VERSION 5.7 ;
BUSBITCHARS "[]" ;
DIVIDERCHAR "/" ;

PROPERTYDEFINITIONS
  MACRO pkpIndependentSourceSHA256 STRING ;
  MACRO CatenaDesignType STRING ;
END PROPERTYDEFINITIONS

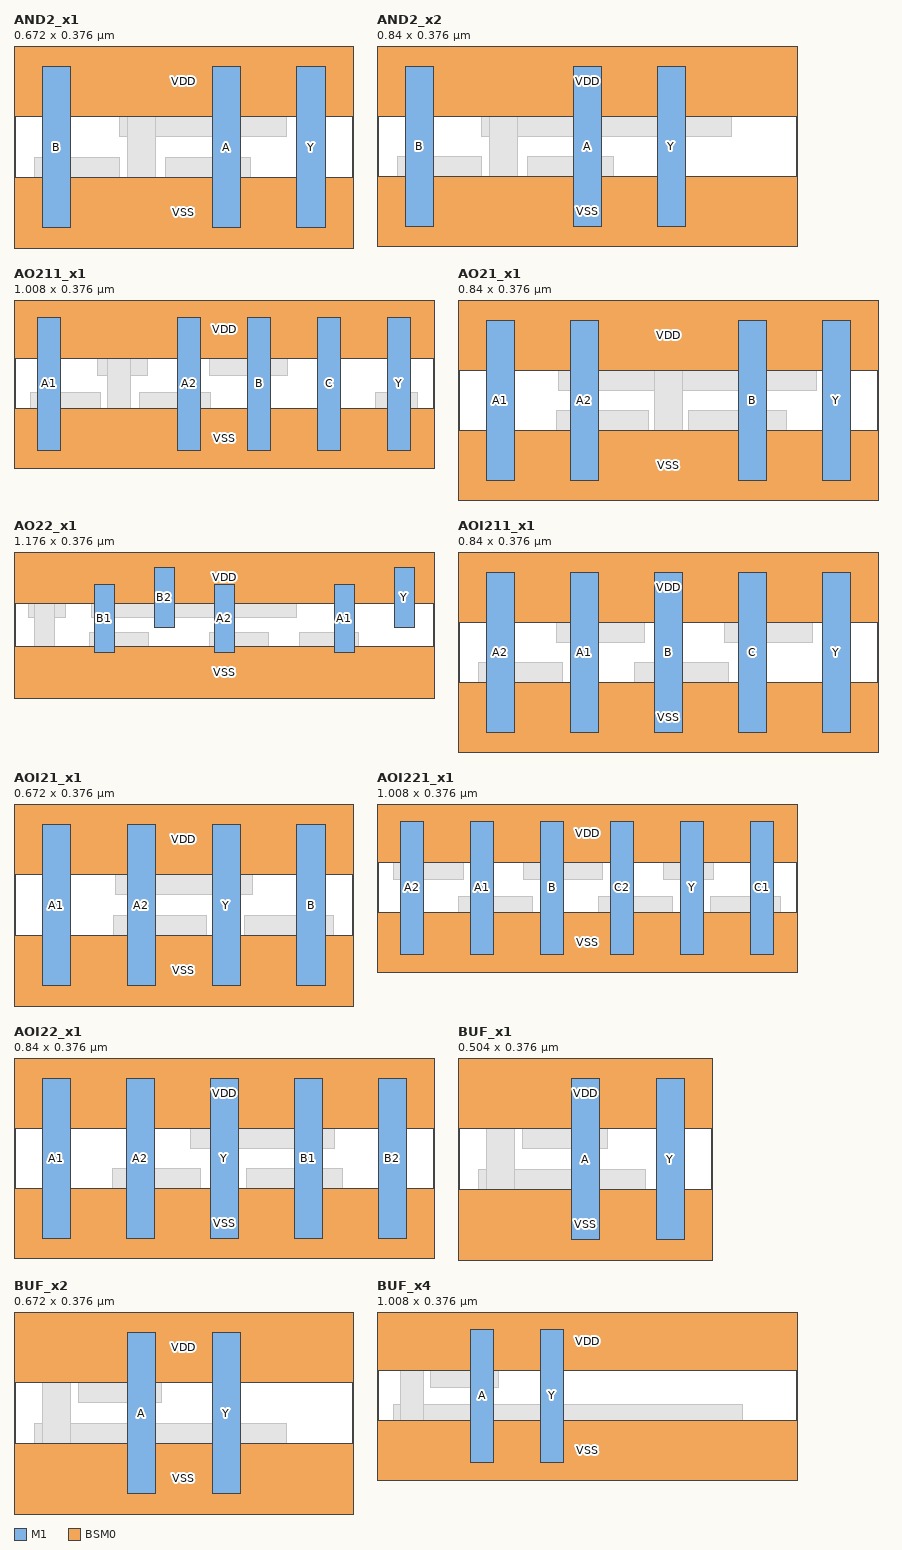
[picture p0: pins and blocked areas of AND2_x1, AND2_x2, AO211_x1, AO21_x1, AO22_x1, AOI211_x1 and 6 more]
MACRO AND2_x1
  CLASS CORE ;
  ORIGIN 0 0 ;
  FOREIGN AND2_x1 0 0 ;
  SIZE 0.672 BY 0.376 ;
  SYMMETRY X Y ;
  SITE CoreSite ;
  PIN A
    DIRECTION INPUT ;
    USE SIGNAL ;
    PORT
      LAYER M1 ;
        RECT 0.392 0.028 0.448 0.348 ;
    END
  END A
  PIN B
    DIRECTION INPUT ;
    USE SIGNAL ;
    PORT
      LAYER M1 ;
        RECT 0.056 0.028 0.112 0.348 ;
    END
  END B
  PIN Y
    DIRECTION OUTPUT ;
    USE SIGNAL ;
    PORT
      LAYER M1 ;
        RECT 0.56 0.028 0.616 0.348 ;
    END
  END Y
  PIN VDD
    DIRECTION INOUT ;
    USE POWER ;
    SHAPE ABUTMENT ;
    PORT
      LAYER BSM0 ;
        RECT 0 0.248 0.672 0.504 ;
    END
  END VDD
  PIN VSS
    DIRECTION INOUT ;
    USE GROUND ;
    SHAPE ABUTMENT ;
    PORT
      LAYER BSM0 ;
        RECT 0 -0.128 0.672 0.128 ;
    END
  END VSS
  OBS
    LAYER M0 ;
      RECT 0.532 0.04 0.632 0.084 ;
      RECT 0.532 0.292 0.632 0.336 ;
      RECT 0.208 0.208 0.54 0.252 ;
      RECT 0.3 0.124 0.468 0.168 ;
      RECT 0.04 0.04 0.32 0.084 ;
      RECT 0.2 0.292 0.32 0.336 ;
      RECT 0.04 0.124 0.208 0.168 ;
    LAYER M1 ;
      RECT 0.224 0.028 0.28 0.348 ;
  END
END AND2_x1

MACRO AND2_x2
  CLASS CORE ;
  ORIGIN 0 0 ;
  FOREIGN AND2_x2 0 0 ;
  SIZE 0.84 BY 0.376 ;
  SYMMETRY X Y ;
  SITE CoreSite ;
  PIN A
    DIRECTION INPUT ;
    USE SIGNAL ;
    PORT
      LAYER M1 ;
        RECT 0.392 0.028 0.448 0.348 ;
    END
  END A
  PIN B
    DIRECTION INPUT ;
    USE SIGNAL ;
    PORT
      LAYER M1 ;
        RECT 0.056 0.028 0.112 0.348 ;
    END
  END B
  PIN Y
    DIRECTION OUTPUT ;
    USE SIGNAL ;
    PORT
      LAYER M1 ;
        RECT 0.56 0.028 0.616 0.348 ;
    END
  END Y
  PIN VDD
    DIRECTION INOUT ;
    USE POWER ;
    SHAPE ABUTMENT ;
    PORT
      LAYER BSM0 ;
        RECT 0 0.248 0.84 0.504 ;
    END
  END VDD
  PIN VSS
    DIRECTION INOUT ;
    USE GROUND ;
    SHAPE ABUTMENT ;
    PORT
      LAYER BSM0 ;
        RECT 0 -0.128 0.84 0.128 ;
    END
  END VSS
  OBS
    LAYER M0 ;
      RECT 0.208 0.208 0.708 0.252 ;
      RECT 0.536 0.04 0.656 0.084 ;
      RECT 0.536 0.292 0.656 0.336 ;
      RECT 0.3 0.124 0.472 0.168 ;
      RECT 0.04 0.04 0.32 0.084 ;
      RECT 0.2 0.292 0.32 0.336 ;
      RECT 0.04 0.124 0.208 0.168 ;
    LAYER M1 ;
      RECT 0.224 0.028 0.28 0.348 ;
  END
END AND2_x2

MACRO AO211_x1
  CLASS CORE ;
  ORIGIN 0 0 ;
  FOREIGN AO211_x1 0 0 ;
  SIZE 1.008 BY 0.376 ;
  SYMMETRY X Y ;
  SITE CoreSite ;
  PIN A1
    DIRECTION INPUT ;
    USE SIGNAL ;
    PORT
      LAYER M1 ;
        RECT 0.056 0.028 0.112 0.348 ;
    END
  END A1
  PIN A2
    DIRECTION INPUT ;
    USE SIGNAL ;
    PORT
      LAYER M1 ;
        RECT 0.392 0.028 0.448 0.348 ;
    END
  END A2
  PIN B
    DIRECTION INPUT ;
    USE SIGNAL ;
    PORT
      LAYER M1 ;
        RECT 0.56 0.028 0.616 0.348 ;
    END
  END B
  PIN C
    DIRECTION INPUT ;
    USE SIGNAL ;
    PORT
      LAYER M1 ;
        RECT 0.728 0.028 0.784 0.348 ;
    END
  END C
  PIN Y
    DIRECTION OUTPUT ;
    USE SIGNAL ;
    PORT
      LAYER M1 ;
        RECT 0.896 0.028 0.952 0.348 ;
    END
  END Y
  PIN VDD
    DIRECTION INOUT ;
    USE POWER ;
    SHAPE ABUTMENT ;
    PORT
      LAYER BSM0 ;
        RECT 0 0.248 1.008 0.504 ;
    END
  END VDD
  PIN VSS
    DIRECTION INOUT ;
    USE GROUND ;
    SHAPE ABUTMENT ;
    PORT
      LAYER BSM0 ;
        RECT 0 -0.128 1.008 0.128 ;
    END
  END VSS
  OBS
    LAYER M0 ;
      RECT 0.868 0.124 0.968 0.168 ;
      RECT 0.868 0.292 0.968 0.336 ;
      RECT 0.04 0.04 0.876 0.084 ;
      RECT 0.636 0.292 0.796 0.336 ;
      RECT 0.468 0.208 0.656 0.252 ;
      RECT 0.3 0.124 0.472 0.168 ;
      RECT 0.048 0.292 0.456 0.336 ;
      RECT 0.2 0.208 0.32 0.252 ;
      RECT 0.04 0.124 0.208 0.168 ;
    LAYER M1 ;
      RECT 0.224 0.028 0.28 0.348 ;
  END
END AO211_x1

MACRO AO21_x1
  CLASS CORE ;
  ORIGIN 0 0 ;
  FOREIGN AO21_x1 0 0 ;
  SIZE 0.84 BY 0.376 ;
  SYMMETRY X Y ;
  SITE CoreSite ;
  PIN A1
    DIRECTION INPUT ;
    USE SIGNAL ;
    PORT
      LAYER M1 ;
        RECT 0.056 0.028 0.112 0.348 ;
    END
  END A1
  PIN A2
    DIRECTION INPUT ;
    USE SIGNAL ;
    PORT
      LAYER M1 ;
        RECT 0.224 0.028 0.28 0.348 ;
    END
  END A2
  PIN B
    DIRECTION INPUT ;
    USE SIGNAL ;
    PORT
      LAYER M1 ;
        RECT 0.56 0.028 0.616 0.348 ;
    END
  END B
  PIN Y
    DIRECTION OUTPUT ;
    USE SIGNAL ;
    PORT
      LAYER M1 ;
        RECT 0.728 0.028 0.784 0.348 ;
    END
  END Y
  PIN VDD
    DIRECTION INOUT ;
    USE POWER ;
    SHAPE ABUTMENT ;
    PORT
      LAYER BSM0 ;
        RECT 0 0.248 0.84 0.504 ;
    END
  END VDD
  PIN VSS
    DIRECTION INOUT ;
    USE GROUND ;
    SHAPE ABUTMENT ;
    PORT
      LAYER BSM0 ;
        RECT 0 -0.128 0.84 0.128 ;
    END
  END VSS
  OBS
    LAYER M0 ;
      RECT 0.688 0.04 0.8 0.084 ;
      RECT 0.688 0.292 0.8 0.336 ;
      RECT 0.2 0.208 0.716 0.252 ;
      RECT 0.46 0.124 0.656 0.168 ;
      RECT 0.352 0.04 0.476 0.084 ;
      RECT 0.04 0.292 0.468 0.336 ;
      RECT 0.196 0.124 0.38 0.168 ;
      RECT 0.04 0.04 0.212 0.084 ;
    LAYER M1 ;
      RECT 0.392 0.028 0.448 0.348 ;
  END
END AO21_x1

MACRO AO22_x1
  CLASS CORE ;
  ORIGIN 0 0 ;
  FOREIGN AO22_x1 0 0 ;
  SIZE 1.176 BY 0.376 ;
  SYMMETRY X Y ;
  SITE CoreSite ;
  PIN A1
    DIRECTION INPUT ;
    USE SIGNAL ;
    PORT
      LAYER M1 ;
        RECT 0.896 0.112 0.952 0.302 ;
    END
  END A1
  PIN A2
    DIRECTION INPUT ;
    USE SIGNAL ;
    PORT
      LAYER M1 ;
        RECT 0.56 0.112 0.616 0.302 ;
    END
  END A2
  PIN B1
    DIRECTION INPUT ;
    USE SIGNAL ;
    PORT
      LAYER M1 ;
        RECT 0.224 0.112 0.28 0.302 ;
    END
  END B1
  PIN B2
    DIRECTION INPUT ;
    USE SIGNAL ;
    PORT
      LAYER M1 ;
        RECT 0.392 0.18 0.448 0.348 ;
    END
  END B2
  PIN Y
    DIRECTION OUTPUT ;
    USE SIGNAL ;
    PORT
      LAYER M1 ;
        RECT 1.064 0.18 1.12 0.348 ;
    END
  END Y
  PIN VDD
    DIRECTION INOUT ;
    USE POWER ;
    SHAPE ABUTMENT ;
    PORT
      LAYER BSM0 ;
        RECT 0 0.248 1.176 0.504 ;
    END
  END VDD
  PIN VSS
    DIRECTION INOUT ;
    USE GROUND ;
    SHAPE ABUTMENT ;
    PORT
      LAYER BSM0 ;
        RECT 0 -0.128 1.176 0.128 ;
    END
  END VSS
  OBS
    LAYER M0 ;
      RECT 1.024 0.292 1.136 0.336 ;
      RECT 0.04 0.04 1.048 0.084 ;
      RECT 0.8 0.124 0.964 0.168 ;
      RECT 0.216 0.208 0.792 0.252 ;
      RECT 0.548 0.124 0.712 0.168 ;
      RECT 0.128 0.292 0.46 0.336 ;
      RECT 0.212 0.124 0.376 0.168 ;
      RECT 0.04 0.208 0.144 0.252 ;
    LAYER M1 ;
      RECT 0.056 0.028 0.112 0.304 ;
  END
  PROPERTY pkpIndependentSourceSHA256 "be00ef7e564fc46890b79b18678042070a181a3fd22f0e1ad2fda87f76c24992" ;
END AO22_x1

MACRO AOI211_x1
  CLASS CORE ;
  ORIGIN 0 0 ;
  FOREIGN AOI211_x1 0 0 ;
  SIZE 0.84 BY 0.376 ;
  SYMMETRY X Y ;
  SITE CoreSite ;
  PIN A1
    DIRECTION INPUT ;
    USE SIGNAL ;
    PORT
      LAYER M1 ;
        RECT 0.224 0.028 0.28 0.348 ;
    END
  END A1
  PIN A2
    DIRECTION INPUT ;
    USE SIGNAL ;
    PORT
      LAYER M1 ;
        RECT 0.056 0.028 0.112 0.348 ;
    END
  END A2
  PIN B
    DIRECTION INPUT ;
    USE SIGNAL ;
    PORT
      LAYER M1 ;
        RECT 0.392 0.028 0.448 0.348 ;
    END
  END B
  PIN C
    DIRECTION INPUT ;
    USE SIGNAL ;
    PORT
      LAYER M1 ;
        RECT 0.56 0.028 0.616 0.348 ;
    END
  END C
  PIN Y
    DIRECTION OUTPUT ;
    USE SIGNAL ;
    PORT
      LAYER M1 ;
        RECT 0.728 0.028 0.784 0.348 ;
    END
  END Y
  PIN VDD
    DIRECTION INOUT ;
    USE POWER ;
    SHAPE ABUTMENT ;
    PORT
      LAYER BSM0 ;
        RECT 0 0.248 0.84 0.504 ;
    END
  END VDD
  PIN VSS
    DIRECTION INOUT ;
    USE GROUND ;
    SHAPE ABUTMENT ;
    PORT
      LAYER BSM0 ;
        RECT 0 -0.128 0.84 0.128 ;
    END
  END VSS
  OBS
    LAYER M0 ;
      RECT 0.384 0.04 0.8 0.084 ;
      RECT 0.688 0.292 0.8 0.336 ;
      RECT 0.532 0.208 0.708 0.252 ;
      RECT 0.352 0.124 0.54 0.168 ;
      RECT 0.048 0.292 0.456 0.336 ;
      RECT 0.196 0.208 0.372 0.252 ;
      RECT 0.04 0.124 0.208 0.168 ;
  END
END AOI211_x1

MACRO AOI21_x1
  CLASS CORE ;
  ORIGIN 0 0 ;
  FOREIGN AOI21_x1 0 0 ;
  SIZE 0.672 BY 0.376 ;
  SYMMETRY X Y ;
  SITE CoreSite ;
  PIN A1
    DIRECTION INPUT ;
    USE SIGNAL ;
    PORT
      LAYER M1 ;
        RECT 0.056 0.028 0.112 0.348 ;
    END
  END A1
  PIN A2
    DIRECTION INPUT ;
    USE SIGNAL ;
    PORT
      LAYER M1 ;
        RECT 0.224 0.028 0.28 0.348 ;
    END
  END A2
  PIN B
    DIRECTION INPUT ;
    USE SIGNAL ;
    PORT
      LAYER M1 ;
        RECT 0.56 0.028 0.616 0.348 ;
    END
  END B
  PIN Y
    DIRECTION OUTPUT ;
    USE SIGNAL ;
    PORT
      LAYER M1 ;
        RECT 0.392 0.028 0.448 0.348 ;
    END
  END Y
  PIN VDD
    DIRECTION INOUT ;
    USE POWER ;
    SHAPE ABUTMENT ;
    PORT
      LAYER BSM0 ;
        RECT 0 0.248 0.672 0.504 ;
    END
  END VDD
  PIN VSS
    DIRECTION INOUT ;
    USE GROUND ;
    SHAPE ABUTMENT ;
    PORT
      LAYER BSM0 ;
        RECT 0 -0.128 0.672 0.128 ;
    END
  END VSS
  OBS
    LAYER M0 ;
      RECT 0.456 0.124 0.632 0.168 ;
      RECT 0.352 0.04 0.472 0.084 ;
      RECT 0.2 0.208 0.472 0.252 ;
      RECT 0.04 0.292 0.472 0.336 ;
      RECT 0.196 0.124 0.38 0.168 ;
      RECT 0.04 0.04 0.208 0.084 ;
  END
END AOI21_x1

MACRO AOI221_x1
  CLASS CORE ;
  ORIGIN 0 0 ;
  FOREIGN AOI221_x1 0 0 ;
  SIZE 1.008 BY 0.376 ;
  SYMMETRY X Y ;
  SITE CoreSite ;
  PIN A1
    DIRECTION INPUT ;
    USE SIGNAL ;
    PORT
      LAYER M1 ;
        RECT 0.224 0.028 0.28 0.348 ;
    END
  END A1
  PIN A2
    DIRECTION INPUT ;
    USE SIGNAL ;
    PORT
      LAYER M1 ;
        RECT 0.056 0.028 0.112 0.348 ;
    END
  END A2
  PIN B
    DIRECTION INPUT ;
    USE SIGNAL ;
    PORT
      LAYER M1 ;
        RECT 0.392 0.028 0.448 0.348 ;
    END
  END B
  PIN C1
    DIRECTION INPUT ;
    USE SIGNAL ;
    PORT
      LAYER M1 ;
        RECT 0.896 0.028 0.952 0.348 ;
    END
  END C1
  PIN C2
    DIRECTION INPUT ;
    USE SIGNAL ;
    PORT
      LAYER M1 ;
        RECT 0.56 0.028 0.616 0.348 ;
    END
  END C2
  PIN Y
    DIRECTION OUTPUT ;
    USE SIGNAL ;
    PORT
      LAYER M1 ;
        RECT 0.728 0.028 0.784 0.348 ;
    END
  END Y
  PIN VDD
    DIRECTION INOUT ;
    USE POWER ;
    SHAPE ABUTMENT ;
    PORT
      LAYER BSM0 ;
        RECT 0 0.248 1.008 0.504 ;
    END
  END VDD
  PIN VSS
    DIRECTION INOUT ;
    USE GROUND ;
    SHAPE ABUTMENT ;
    PORT
      LAYER BSM0 ;
        RECT 0 -0.128 1.008 0.128 ;
    END
  END VSS
  OBS
    LAYER M0 ;
      RECT 0.8 0.124 0.968 0.168 ;
      RECT 0.384 0.04 0.96 0.084 ;
      RECT 0.552 0.292 0.96 0.336 ;
      RECT 0.688 0.208 0.808 0.252 ;
      RECT 0.532 0.124 0.708 0.168 ;
      RECT 0.352 0.208 0.54 0.252 ;
      RECT 0.048 0.292 0.456 0.336 ;
      RECT 0.196 0.124 0.372 0.168 ;
      RECT 0.04 0.208 0.208 0.252 ;
  END
END AOI221_x1

MACRO AOI22_x1
  CLASS CORE ;
  ORIGIN 0 0 ;
  FOREIGN AOI22_x1 0 0 ;
  SIZE 0.84 BY 0.376 ;
  SYMMETRY X Y ;
  SITE CoreSite ;
  PIN A1
    DIRECTION INPUT ;
    USE SIGNAL ;
    PORT
      LAYER M1 ;
        RECT 0.056 0.028 0.112 0.348 ;
    END
  END A1
  PIN A2
    DIRECTION INPUT ;
    USE SIGNAL ;
    PORT
      LAYER M1 ;
        RECT 0.224 0.028 0.28 0.348 ;
    END
  END A2
  PIN B1
    DIRECTION INPUT ;
    USE SIGNAL ;
    PORT
      LAYER M1 ;
        RECT 0.56 0.028 0.616 0.348 ;
    END
  END B1
  PIN B2
    DIRECTION INPUT ;
    USE SIGNAL ;
    PORT
      LAYER M1 ;
        RECT 0.728 0.028 0.784 0.348 ;
    END
  END B2
  PIN Y
    DIRECTION OUTPUT ;
    USE SIGNAL ;
    PORT
      LAYER M1 ;
        RECT 0.392 0.028 0.448 0.348 ;
    END
  END Y
  PIN VDD
    DIRECTION INOUT ;
    USE POWER ;
    SHAPE ABUTMENT ;
    PORT
      LAYER BSM0 ;
        RECT 0 0.248 0.84 0.504 ;
    END
  END VDD
  PIN VSS
    DIRECTION INOUT ;
    USE GROUND ;
    SHAPE ABUTMENT ;
    PORT
      LAYER BSM0 ;
        RECT 0 -0.128 0.84 0.128 ;
    END
  END VSS
  OBS
    LAYER M0 ;
      RECT 0.624 0.04 0.8 0.084 ;
      RECT 0.04 0.292 0.8 0.336 ;
      RECT 0.464 0.124 0.656 0.168 ;
      RECT 0.352 0.208 0.64 0.252 ;
      RECT 0.352 0.04 0.476 0.084 ;
      RECT 0.196 0.124 0.372 0.168 ;
      RECT 0.044 0.04 0.208 0.084 ;
  END
  PROPERTY CatenaDesignType "deviceLevel" ;
END AOI22_x1

MACRO BUF_x1
  CLASS CORE ;
  ORIGIN 0 0 ;
  FOREIGN BUF_x1 0 0 ;
  SIZE 0.504 BY 0.376 ;
  SYMMETRY X Y ;
  SITE CoreSite ;
  PIN A
    DIRECTION INPUT ;
    USE SIGNAL ;
    PORT
      LAYER M1 ;
        RECT 0.224 0.028 0.28 0.348 ;
    END
  END A
  PIN Y
    DIRECTION OUTPUT ;
    USE SIGNAL ;
    PORT
      LAYER M1 ;
        RECT 0.392 0.028 0.448 0.348 ;
    END
  END Y
  PIN VDD
    DIRECTION INOUT ;
    USE POWER ;
    SHAPE ABUTMENT ;
    PORT
      LAYER BSM0 ;
        RECT 0 0.248 0.504 0.504 ;
    END
  END VDD
  PIN VSS
    DIRECTION INOUT ;
    USE GROUND ;
    SHAPE ABUTMENT ;
    PORT
      LAYER BSM0 ;
        RECT 0 -0.128 0.504 0.128 ;
    END
  END VSS
  OBS
    LAYER M0 ;
      RECT 0.352 0.04 0.464 0.084 ;
      RECT 0.352 0.292 0.464 0.336 ;
      RECT 0.04 0.124 0.372 0.168 ;
      RECT 0.128 0.208 0.296 0.252 ;
      RECT 0.04 0.04 0.14 0.084 ;
      RECT 0.04 0.292 0.14 0.336 ;
    LAYER M1 ;
      RECT 0.056 0.028 0.112 0.348 ;
  END
END BUF_x1

MACRO BUF_x2
  CLASS CORE ;
  ORIGIN 0 0 ;
  FOREIGN BUF_x2 0 0 ;
  SIZE 0.672 BY 0.376 ;
  SYMMETRY X Y ;
  SITE CoreSite ;
  PIN A
    DIRECTION INPUT ;
    USE SIGNAL ;
    PORT
      LAYER M1 ;
        RECT 0.224 0.028 0.28 0.348 ;
    END
  END A
  PIN Y
    DIRECTION OUTPUT ;
    USE SIGNAL ;
    PORT
      LAYER M1 ;
        RECT 0.392 0.028 0.448 0.348 ;
    END
  END Y
  PIN VDD
    DIRECTION INOUT ;
    USE POWER ;
    SHAPE ABUTMENT ;
    PORT
      LAYER BSM0 ;
        RECT 0 0.248 0.672 0.504 ;
    END
  END VDD
  PIN VSS
    DIRECTION INOUT ;
    USE GROUND ;
    SHAPE ABUTMENT ;
    PORT
      LAYER BSM0 ;
        RECT 0 -0.128 0.672 0.128 ;
    END
  END VSS
  OBS
    LAYER M0 ;
      RECT 0.04 0.124 0.54 0.168 ;
      RECT 0.352 0.04 0.472 0.084 ;
      RECT 0.352 0.292 0.472 0.336 ;
      RECT 0.128 0.208 0.292 0.252 ;
      RECT 0.04 0.04 0.14 0.084 ;
      RECT 0.04 0.292 0.14 0.336 ;
    LAYER M1 ;
      RECT 0.056 0.028 0.112 0.348 ;
  END
END BUF_x2

MACRO BUF_x4
  CLASS CORE ;
  ORIGIN 0 0 ;
  FOREIGN BUF_x4 0 0 ;
  SIZE 1.008 BY 0.376 ;
  SYMMETRY X Y ;
  SITE CoreSite ;
  PIN A
    DIRECTION INPUT ;
    USE SIGNAL ;
    PORT
      LAYER M1 ;
        RECT 0.224 0.028 0.28 0.348 ;
    END
  END A
  PIN Y
    DIRECTION OUTPUT ;
    USE SIGNAL ;
    PORT
      LAYER M1 ;
        RECT 0.392 0.028 0.448 0.348 ;
    END
  END Y
  PIN VDD
    DIRECTION INOUT ;
    USE POWER ;
    SHAPE ABUTMENT ;
    PORT
      LAYER BSM0 ;
        RECT 0 0.248 1.008 0.504 ;
    END
  END VDD
  PIN VSS
    DIRECTION INOUT ;
    USE GROUND ;
    SHAPE ABUTMENT ;
    PORT
      LAYER BSM0 ;
        RECT 0 -0.128 1.008 0.128 ;
    END
  END VSS
  OBS
    LAYER M0 ;
      RECT 0.04 0.124 0.876 0.168 ;
      RECT 0.368 0.04 0.796 0.084 ;
      RECT 0.368 0.292 0.796 0.336 ;
      RECT 0.128 0.208 0.292 0.252 ;
      RECT 0.04 0.04 0.14 0.084 ;
      RECT 0.04 0.292 0.14 0.336 ;
    LAYER M1 ;
      RECT 0.056 0.028 0.112 0.348 ;
  END
END BUF_x4

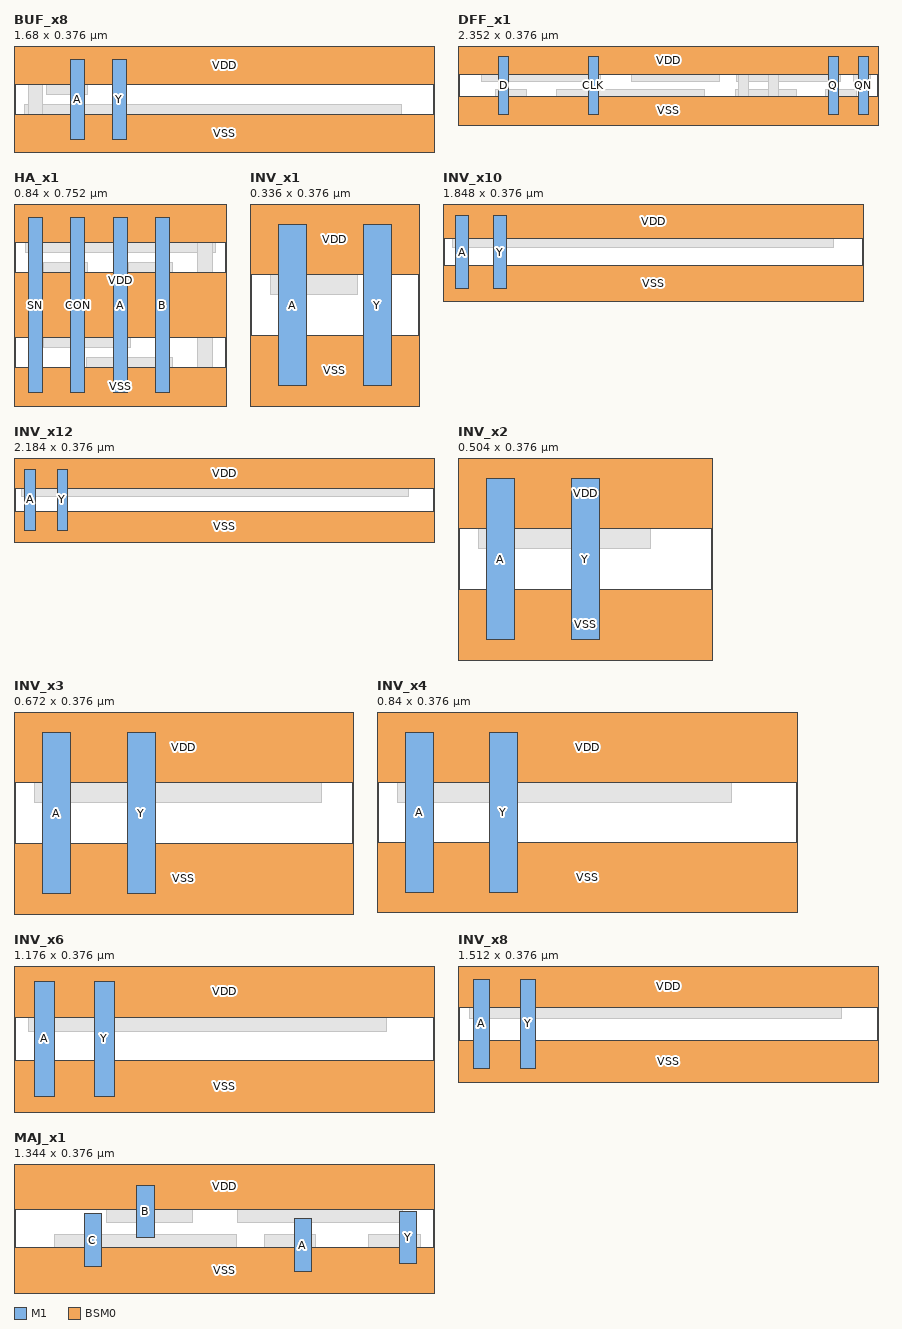
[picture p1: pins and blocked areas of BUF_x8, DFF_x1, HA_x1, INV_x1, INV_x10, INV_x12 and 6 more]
MACRO BUF_x8
  CLASS CORE ;
  ORIGIN 0 0 ;
  FOREIGN BUF_x8 0 0 ;
  SIZE 1.68 BY 0.376 ;
  SYMMETRY X Y ;
  SITE CoreSite ;
  PIN A
    DIRECTION INPUT ;
    USE SIGNAL ;
    PORT
      LAYER M1 ;
        RECT 0.224 0.028 0.28 0.348 ;
    END
  END A
  PIN Y
    DIRECTION OUTPUT ;
    USE SIGNAL ;
    PORT
      LAYER M1 ;
        RECT 0.392 0.028 0.448 0.348 ;
    END
  END Y
  PIN VDD
    DIRECTION INOUT ;
    USE POWER ;
    SHAPE ABUTMENT ;
    PORT
      LAYER BSM0 ;
        RECT 0 0.248 1.68 0.504 ;
    END
  END VDD
  PIN VSS
    DIRECTION INOUT ;
    USE GROUND ;
    SHAPE ABUTMENT ;
    PORT
      LAYER BSM0 ;
        RECT 0 -0.128 1.68 0.128 ;
    END
  END VSS
  OBS
    LAYER M0 ;
      RECT 0.04 0.124 1.548 0.168 ;
      RECT 0.368 0.04 1.468 0.084 ;
      RECT 0.368 0.292 1.468 0.336 ;
      RECT 0.128 0.208 0.292 0.252 ;
      RECT 0.04 0.04 0.14 0.084 ;
      RECT 0.04 0.292 0.14 0.336 ;
    LAYER M1 ;
      RECT 0.056 0.028 0.112 0.348 ;
  END
END BUF_x8

MACRO DFF_x1
  CLASS CORE ;
  ORIGIN 0 0 ;
  FOREIGN DFF_x1 0 0 ;
  SIZE 2.352 BY 0.376 ;
  SYMMETRY X Y ;
  SITE CoreSite ;
  PIN CLK
    DIRECTION INPUT ;
    USE CLOCK ;
    PORT
      LAYER M1 ;
        RECT 0.728 0.028 0.784 0.348 ;
    END
  END CLK
  PIN D
    DIRECTION INPUT ;
    USE SIGNAL ;
    PORT
      LAYER M1 ;
        RECT 0.224 0.028 0.28 0.348 ;
    END
  END D
  PIN Q
    DIRECTION OUTPUT ;
    USE SIGNAL ;
    PORT
      LAYER M1 ;
        RECT 2.072 0.028 2.128 0.348 ;
    END
  END Q
  PIN QN
    DIRECTION OUTPUT ;
    USE SIGNAL ;
    PORT
      LAYER M1 ;
        RECT 2.24 0.028 2.296 0.348 ;
    END
  END QN
  PIN VDD
    DIRECTION INOUT ;
    USE POWER ;
    SHAPE ABUTMENT ;
    PORT
      LAYER BSM0 ;
        RECT 0 0.248 2.352 0.504 ;
    END
  END VDD
  PIN VSS
    DIRECTION INOUT ;
    USE GROUND ;
    SHAPE ABUTMENT ;
    PORT
      LAYER BSM0 ;
        RECT 0 -0.128 2.352 0.128 ;
    END
  END VSS
  OBS
    LAYER M0 ;
      RECT 2.212 0.208 2.312 0.252 ;
      RECT 1.98 0.04 2.308 0.084 ;
      RECT 2.06 0.124 2.234 0.168 ;
      RECT 1.56 0.208 2.14 0.252 ;
      RECT 1.556 0.124 1.898 0.168 ;
      RECT 1.724 0.292 1.898 0.336 ;
      RECT 0.716 0.04 1.804 0.084 ;
      RECT 0.048 0.292 1.636 0.336 ;
      RECT 0.972 0.208 1.464 0.252 ;
      RECT 0.552 0.124 1.38 0.168 ;
      RECT 0.132 0.208 0.796 0.252 ;
      RECT 0.048 0.04 0.54 0.084 ;
      RECT 0.212 0.124 0.386 0.168 ;
    LAYER M1 ;
      RECT 1.736 0.028 1.792 0.348 ;
      RECT 1.568 0.028 1.624 0.348 ;
  END
END DFF_x1

MACRO HA_x1
  CLASS CORE ;
  ORIGIN 0 0 ;
  FOREIGN HA_x1 0 0 ;
  SIZE 0.84 BY 0.752 ;
  SYMMETRY X Y ;
  SITE CoreSite ;
  PIN A
    DIRECTION INPUT ;
    USE SIGNAL ;
    PORT
      LAYER M1 ;
        RECT 0.392 0.028 0.448 0.724 ;
    END
  END A
  PIN B
    DIRECTION INPUT ;
    USE SIGNAL ;
    PORT
      LAYER M1 ;
        RECT 0.56 0.028 0.616 0.724 ;
    END
  END B
  PIN CON
    DIRECTION OUTPUT ;
    USE SIGNAL ;
    PORT
      LAYER M1 ;
        RECT 0.224 0.028 0.28 0.724 ;
    END
  END CON
  PIN SN
    DIRECTION OUTPUT ;
    USE SIGNAL ;
    PORT
      LAYER M1 ;
        RECT 0.056 0.028 0.112 0.724 ;
    END
  END SN
  PIN VDD
    DIRECTION INOUT ;
    USE POWER ;
    SHAPE ABUTMENT ;
    PORT
      LAYER BSM0 ;
        RECT 0 0.248 0.84 0.504 ;
    END
  END VDD
  PIN VSS
    DIRECTION INOUT ;
    USE GROUND ;
    SHAPE ABUTMENT ;
    PORT
      LAYER BSM0 ;
        RECT 0 -0.128 0.84 0.128 ;
        RECT 0 0.624 0.84 0.88 ;
    END
  END VSS
  OBS
    LAYER M0 ;
      RECT 0.538 0.416 0.796 0.46 ;
      RECT 0.044 0.584 0.796 0.628 ;
      RECT 0.286 0.124 0.628 0.168 ;
      RECT 0.454 0.5 0.628 0.544 ;
      RECT 0.216 0.668 0.624 0.712 ;
      RECT 0.212 0.04 0.47 0.084 ;
      RECT 0.118 0.208 0.46 0.252 ;
      RECT 0.286 0.416 0.46 0.46 ;
      RECT 0.048 0.292 0.456 0.336 ;
      RECT 0.118 0.5 0.292 0.544 ;
      RECT 0.04 0.416 0.14 0.46 ;
    LAYER M1 ;
      RECT 0.728 0.028 0.784 0.724 ;
  END
END HA_x1

MACRO INV_x1
  CLASS CORE ;
  ORIGIN 0 0 ;
  FOREIGN INV_x1 0 0 ;
  SIZE 0.336 BY 0.376 ;
  SYMMETRY X Y ;
  SITE CoreSite ;
  PIN A
    DIRECTION INPUT ;
    USE SIGNAL ;
    PORT
      LAYER M1 ;
        RECT 0.056 0.028 0.112 0.348 ;
    END
  END A
  PIN Y
    DIRECTION OUTPUT ;
    USE SIGNAL ;
    PORT
      LAYER M1 ;
        RECT 0.224 0.028 0.28 0.348 ;
    END
  END Y
  PIN VDD
    DIRECTION INOUT ;
    USE POWER ;
    SHAPE ABUTMENT ;
    PORT
      LAYER BSM0 ;
        RECT 0 0.248 0.336 0.504 ;
    END
  END VDD
  PIN VSS
    DIRECTION INOUT ;
    USE GROUND ;
    SHAPE ABUTMENT ;
    PORT
      LAYER BSM0 ;
        RECT 0 -0.128 0.336 0.128 ;
    END
  END VSS
  OBS
    LAYER M0 ;
      RECT 0.128 0.04 0.296 0.084 ;
      RECT 0.128 0.292 0.296 0.336 ;
      RECT 0.04 0.208 0.212 0.252 ;
  END
END INV_x1

MACRO INV_x10
  CLASS CORE ;
  ORIGIN 0 0 ;
  FOREIGN INV_x10 0 0 ;
  SIZE 1.848 BY 0.376 ;
  SYMMETRY X Y ;
  SITE CoreSite ;
  PIN A
    DIRECTION INPUT ;
    USE SIGNAL ;
    PORT
      LAYER M1 ;
        RECT 0.056 0.028 0.112 0.348 ;
    END
  END A
  PIN Y
    DIRECTION OUTPUT ;
    USE SIGNAL ;
    PORT
      LAYER M1 ;
        RECT 0.224 0.028 0.28 0.348 ;
    END
  END Y
  PIN VDD
    DIRECTION INOUT ;
    USE POWER ;
    SHAPE ABUTMENT ;
    PORT
      LAYER BSM0 ;
        RECT 0 0.248 1.848 0.504 ;
    END
  END VDD
  PIN VSS
    DIRECTION INOUT ;
    USE GROUND ;
    SHAPE ABUTMENT ;
    PORT
      LAYER BSM0 ;
        RECT 0 -0.128 1.848 0.128 ;
    END
  END VSS
  OBS
    LAYER M0 ;
      RECT 0.04 0.208 1.716 0.252 ;
      RECT 0.2 0.04 1.64 0.084 ;
      RECT 0.2 0.292 1.636 0.336 ;
  END
END INV_x10

MACRO INV_x12
  CLASS CORE ;
  ORIGIN 0 0 ;
  FOREIGN INV_x12 0 0 ;
  SIZE 2.184 BY 0.376 ;
  SYMMETRY X Y ;
  SITE CoreSite ;
  PIN A
    DIRECTION INPUT ;
    USE SIGNAL ;
    PORT
      LAYER M1 ;
        RECT 0.056 0.028 0.112 0.348 ;
    END
  END A
  PIN Y
    DIRECTION OUTPUT ;
    USE SIGNAL ;
    PORT
      LAYER M1 ;
        RECT 0.224 0.028 0.28 0.348 ;
    END
  END Y
  PIN VDD
    DIRECTION INOUT ;
    USE POWER ;
    SHAPE ABUTMENT ;
    PORT
      LAYER BSM0 ;
        RECT 0 0.248 2.184 0.504 ;
    END
  END VDD
  PIN VSS
    DIRECTION INOUT ;
    USE GROUND ;
    SHAPE ABUTMENT ;
    PORT
      LAYER BSM0 ;
        RECT 0 -0.128 2.184 0.128 ;
    END
  END VSS
  OBS
    LAYER M0 ;
      RECT 0.04 0.208 2.052 0.252 ;
      RECT 0.2 0.04 1.972 0.084 ;
      RECT 0.2 0.292 1.972 0.336 ;
  END
END INV_x12

MACRO INV_x2
  CLASS CORE ;
  ORIGIN 0 0 ;
  FOREIGN INV_x2 0 0 ;
  SIZE 0.504 BY 0.376 ;
  SYMMETRY X Y ;
  SITE CoreSite ;
  PIN A
    DIRECTION INPUT ;
    USE SIGNAL ;
    PORT
      LAYER M1 ;
        RECT 0.056 0.028 0.112 0.348 ;
    END
  END A
  PIN Y
    DIRECTION OUTPUT ;
    USE SIGNAL ;
    PORT
      LAYER M1 ;
        RECT 0.224 0.028 0.28 0.348 ;
    END
  END Y
  PIN VDD
    DIRECTION INOUT ;
    USE POWER ;
    SHAPE ABUTMENT ;
    PORT
      LAYER BSM0 ;
        RECT 0 0.248 0.504 0.504 ;
    END
  END VDD
  PIN VSS
    DIRECTION INOUT ;
    USE GROUND ;
    SHAPE ABUTMENT ;
    PORT
      LAYER BSM0 ;
        RECT 0 -0.128 0.504 0.128 ;
    END
  END VSS
  OBS
    LAYER M0 ;
      RECT 0.04 0.208 0.38 0.252 ;
      RECT 0.2 0.04 0.32 0.084 ;
      RECT 0.2 0.292 0.32 0.336 ;
  END
END INV_x2

MACRO INV_x3
  CLASS CORE ;
  ORIGIN 0 0 ;
  FOREIGN INV_x3 0 0 ;
  SIZE 0.672 BY 0.376 ;
  SYMMETRY X Y ;
  SITE CoreSite ;
  PIN A
    DIRECTION INPUT ;
    USE SIGNAL ;
    PORT
      LAYER M1 ;
        RECT 0.056 0.028 0.112 0.348 ;
    END
  END A
  PIN Y
    DIRECTION OUTPUT ;
    USE SIGNAL ;
    PORT
      LAYER M1 ;
        RECT 0.224 0.028 0.28 0.348 ;
    END
  END Y
  PIN VDD
    DIRECTION INOUT ;
    USE POWER ;
    SHAPE ABUTMENT ;
    PORT
      LAYER BSM0 ;
        RECT 0 0.248 0.672 0.504 ;
    END
  END VDD
  PIN VSS
    DIRECTION INOUT ;
    USE GROUND ;
    SHAPE ABUTMENT ;
    PORT
      LAYER BSM0 ;
        RECT 0 -0.128 0.672 0.128 ;
    END
  END VSS
  OBS
    LAYER M0 ;
      RECT 0.2 0.04 0.628 0.084 ;
      RECT 0.2 0.292 0.628 0.336 ;
      RECT 0.04 0.208 0.608 0.252 ;
  END
END INV_x3

MACRO INV_x4
  CLASS CORE ;
  ORIGIN 0 0 ;
  FOREIGN INV_x4 0 0 ;
  SIZE 0.84 BY 0.376 ;
  SYMMETRY X Y ;
  SITE CoreSite ;
  PIN A
    DIRECTION INPUT ;
    USE SIGNAL ;
    PORT
      LAYER M1 ;
        RECT 0.056 0.028 0.112 0.348 ;
    END
  END A
  PIN Y
    DIRECTION OUTPUT ;
    USE SIGNAL ;
    PORT
      LAYER M1 ;
        RECT 0.224 0.028 0.28 0.348 ;
    END
  END Y
  PIN VDD
    DIRECTION INOUT ;
    USE POWER ;
    SHAPE ABUTMENT ;
    PORT
      LAYER BSM0 ;
        RECT 0 0.248 0.84 0.504 ;
    END
  END VDD
  PIN VSS
    DIRECTION INOUT ;
    USE GROUND ;
    SHAPE ABUTMENT ;
    PORT
      LAYER BSM0 ;
        RECT 0 -0.128 0.84 0.128 ;
    END
  END VSS
  OBS
    LAYER M0 ;
      RECT 0.04 0.208 0.708 0.252 ;
      RECT 0.2 0.04 0.628 0.084 ;
      RECT 0.2 0.292 0.628 0.336 ;
  END
END INV_x4

MACRO INV_x6
  CLASS CORE ;
  ORIGIN 0 0 ;
  FOREIGN INV_x6 0 0 ;
  SIZE 1.176 BY 0.376 ;
  SYMMETRY X Y ;
  SITE CoreSite ;
  PIN A
    DIRECTION INPUT ;
    USE SIGNAL ;
    PORT
      LAYER M1 ;
        RECT 0.056 0.028 0.112 0.348 ;
    END
  END A
  PIN Y
    DIRECTION OUTPUT ;
    USE SIGNAL ;
    PORT
      LAYER M1 ;
        RECT 0.224 0.028 0.28 0.348 ;
    END
  END Y
  PIN VDD
    DIRECTION INOUT ;
    USE POWER ;
    SHAPE ABUTMENT ;
    PORT
      LAYER BSM0 ;
        RECT 0 0.248 1.176 0.504 ;
    END
  END VDD
  PIN VSS
    DIRECTION INOUT ;
    USE GROUND ;
    SHAPE ABUTMENT ;
    PORT
      LAYER BSM0 ;
        RECT 0 -0.128 1.176 0.128 ;
    END
  END VSS
  OBS
    LAYER M0 ;
      RECT 0.04 0.208 1.044 0.252 ;
      RECT 0.2 0.04 0.964 0.084 ;
      RECT 0.2 0.292 0.964 0.336 ;
  END
END INV_x6

MACRO INV_x8
  CLASS CORE ;
  ORIGIN 0 0 ;
  FOREIGN INV_x8 0 0 ;
  SIZE 1.512 BY 0.376 ;
  SYMMETRY X Y ;
  SITE CoreSite ;
  PIN A
    DIRECTION INPUT ;
    USE SIGNAL ;
    PORT
      LAYER M1 ;
        RECT 0.056 0.028 0.112 0.348 ;
    END
  END A
  PIN Y
    DIRECTION OUTPUT ;
    USE SIGNAL ;
    PORT
      LAYER M1 ;
        RECT 0.224 0.028 0.28 0.348 ;
    END
  END Y
  PIN VDD
    DIRECTION INOUT ;
    USE POWER ;
    SHAPE ABUTMENT ;
    PORT
      LAYER BSM0 ;
        RECT 0 0.248 1.512 0.504 ;
    END
  END VDD
  PIN VSS
    DIRECTION INOUT ;
    USE GROUND ;
    SHAPE ABUTMENT ;
    PORT
      LAYER BSM0 ;
        RECT 0 -0.128 1.512 0.128 ;
    END
  END VSS
  OBS
    LAYER M0 ;
      RECT 0.04 0.208 1.38 0.252 ;
      RECT 0.2 0.04 1.3 0.084 ;
      RECT 0.2 0.292 1.3 0.336 ;
  END
END INV_x8

MACRO MAJ_x1
  CLASS CORE ;
  ORIGIN 0 0 ;
  FOREIGN MAJ_x1 0 0 ;
  SIZE 1.344 BY 0.376 ;
  SYMMETRY X Y ;
  SITE CoreSite ;
  PIN A
    DIRECTION INPUT ;
    USE SIGNAL ;
    PORT
      LAYER M1 ;
        RECT 0.896 0.05 0.952 0.218 ;
    END
  END A
  PIN B
    DIRECTION INPUT ;
    USE SIGNAL ;
    PORT
      LAYER M1 ;
        RECT 0.392 0.158 0.448 0.326 ;
    END
  END B
  PIN C
    DIRECTION INPUT ;
    USE SIGNAL ;
    PORT
      LAYER M1 ;
        RECT 0.224 0.066 0.28 0.234 ;
    END
  END C
  PIN Y
    DIRECTION OUTPUT ;
    USE SIGNAL ;
    PORT
      LAYER M1 ;
        RECT 1.232 0.074 1.288 0.242 ;
    END
  END Y
  PIN VDD
    DIRECTION INOUT ;
    USE POWER ;
    SHAPE ABUTMENT ;
    PORT
      LAYER BSM0 ;
        RECT 0 0.248 1.344 0.504 ;
    END
  END VDD
  PIN VSS
    DIRECTION INOUT ;
    USE GROUND ;
    SHAPE ABUTMENT ;
    PORT
      LAYER BSM0 ;
        RECT 0 -0.128 1.344 0.128 ;
    END
  END VSS
  OBS
    LAYER M0 ;
      RECT 1.136 0.124 1.3 0.168 ;
      RECT 0.716 0.208 1.244 0.252 ;
      RECT 0.212 0.292 1.02 0.336 ;
      RECT 0.212 0.04 0.964 0.084 ;
      RECT 0.8 0.124 0.964 0.168 ;
      RECT 0.128 0.124 0.712 0.168 ;
      RECT 0.296 0.208 0.572 0.252 ;
  END
  PROPERTY pkpIndependentSourceSHA256 "c6524f313f9f278eef24616a36d5740bf9d2db56e62a49f5a092eda3790d412a" ;
END MAJ_x1

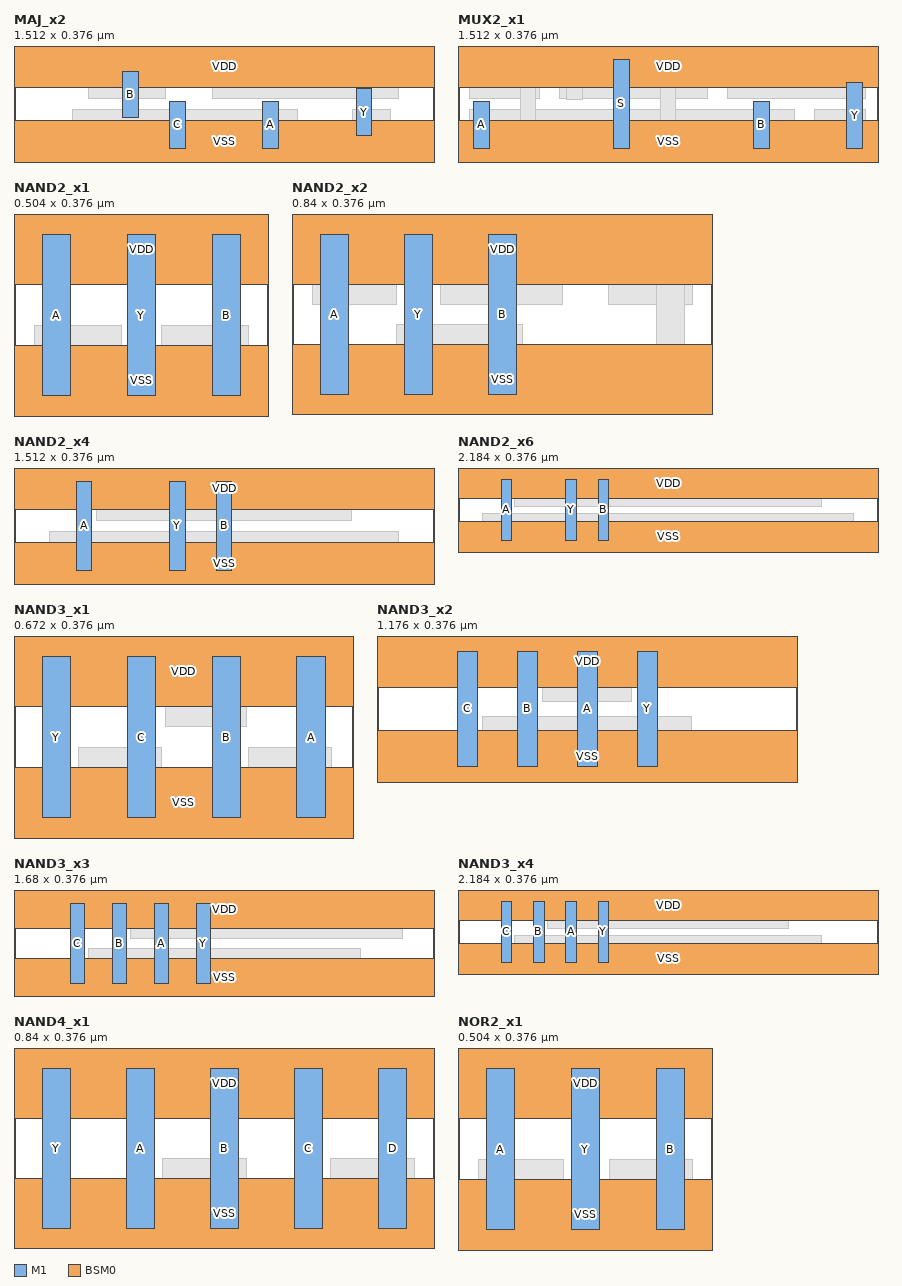
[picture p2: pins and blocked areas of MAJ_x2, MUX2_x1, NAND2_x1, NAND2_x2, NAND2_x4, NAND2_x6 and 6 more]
MACRO MAJ_x2
  CLASS CORE ;
  ORIGIN 0 0 ;
  FOREIGN MAJ_x2 0 0 ;
  SIZE 1.512 BY 0.376 ;
  SYMMETRY X Y ;
  SITE CoreSite ;
  PIN A
    DIRECTION INPUT ;
    USE SIGNAL ;
    PORT
      LAYER M1 ;
        RECT 0.896 0.028 0.952 0.196 ;
    END
  END A
  PIN B
    DIRECTION INPUT ;
    USE SIGNAL ;
    PORT
      LAYER M1 ;
        RECT 0.392 0.138 0.448 0.306 ;
    END
  END B
  PIN C
    DIRECTION INPUT ;
    USE SIGNAL ;
    PORT
      LAYER M1 ;
        RECT 0.56 0.028 0.616 0.196 ;
    END
  END C
  PIN Y
    DIRECTION OUTPUT ;
    USE SIGNAL ;
    PORT
      LAYER M1 ;
        RECT 1.232 0.074 1.288 0.242 ;
    END
  END Y
  PIN VDD
    DIRECTION INOUT ;
    USE POWER ;
    SHAPE ABUTMENT ;
    PORT
      LAYER BSM0 ;
        RECT 0 0.248 1.512 0.504 ;
    END
  END VDD
  PIN VSS
    DIRECTION INOUT ;
    USE GROUND ;
    SHAPE ABUTMENT ;
    PORT
      LAYER BSM0 ;
        RECT 0 -0.128 1.512 0.128 ;
    END
  END VSS
  OBS
    LAYER M0 ;
      RECT 0.716 0.208 1.384 0.252 ;
      RECT 1.22 0.124 1.356 0.168 ;
      RECT 0.212 0.124 1.02 0.168 ;
      RECT 0.8 0.04 0.964 0.084 ;
      RECT 0.212 0.292 0.964 0.336 ;
      RECT 0.128 0.04 0.712 0.084 ;
      RECT 0.268 0.208 0.544 0.252 ;
  END
  PROPERTY pkpIndependentSourceSHA256 "503b818806f41a63dad2466f29618c257b77dd42f9f3fecf4337ea01a5ae6336" ;
END MAJ_x2

MACRO MUX2_x1
  CLASS CORE ;
  ORIGIN 0 0 ;
  FOREIGN MUX2_x1 0 0 ;
  SIZE 1.512 BY 0.376 ;
  SYMMETRY X Y ;
  SITE CoreSite ;
  PIN A
    DIRECTION INPUT ;
    USE SIGNAL ;
    PORT
      LAYER M1 ;
        RECT 0.056 0.028 0.112 0.196 ;
    END
  END A
  PIN B
    DIRECTION INPUT ;
    USE SIGNAL ;
    PORT
      LAYER M1 ;
        RECT 1.064 0.028 1.12 0.196 ;
    END
  END B
  PIN S
    DIRECTION INPUT ;
    USE SIGNAL ;
    PORT
      LAYER M1 ;
        RECT 0.56 0.028 0.616 0.348 ;
    END
  END S
  PIN Y
    DIRECTION OUTPUT ;
    USE SIGNAL ;
    PORT
      LAYER M1 ;
        RECT 1.4 0.028 1.456 0.264 ;
    END
  END Y
  PIN VDD
    DIRECTION INOUT ;
    USE POWER ;
    SHAPE ABUTMENT ;
    PORT
      LAYER BSM0 ;
        RECT 0 0.248 1.512 0.504 ;
    END
  END VDD
  PIN VSS
    DIRECTION INOUT ;
    USE GROUND ;
    SHAPE ABUTMENT ;
    PORT
      LAYER BSM0 ;
        RECT 0 -0.128 1.512 0.128 ;
    END
  END VSS
  OBS
    LAYER M0 ;
      RECT 1.284 0.124 1.468 0.168 ;
      RECT 0.97 0.208 1.468 0.252 ;
      RECT 0.696 0.292 1.384 0.336 ;
      RECT 0.972 0.04 1.214 0.084 ;
      RECT 0.04 0.124 1.212 0.168 ;
      RECT 0.7 0.04 0.9 0.084 ;
      RECT 0.364 0.208 0.898 0.252 ;
      RECT 0.444 0.04 0.628 0.084 ;
      RECT 0.132 0.292 0.624 0.336 ;
      RECT 0.04 0.04 0.372 0.084 ;
      RECT 0.04 0.208 0.292 0.252 ;
    LAYER M1 ;
      RECT 0.728 0.028 0.784 0.348 ;
      RECT 0.392 0.204 0.448 0.348 ;
      RECT 0.224 0.028 0.28 0.264 ;
  END
END MUX2_x1

MACRO NAND2_x1
  CLASS CORE ;
  ORIGIN 0 0 ;
  FOREIGN NAND2_x1 0 0 ;
  SIZE 0.504 BY 0.376 ;
  SYMMETRY X Y ;
  SITE CoreSite ;
  PIN A
    DIRECTION INPUT ;
    USE SIGNAL ;
    PORT
      LAYER M1 ;
        RECT 0.056 0.028 0.112 0.348 ;
    END
  END A
  PIN B
    DIRECTION INPUT ;
    USE SIGNAL ;
    PORT
      LAYER M1 ;
        RECT 0.392 0.028 0.448 0.348 ;
    END
  END B
  PIN Y
    DIRECTION OUTPUT ;
    USE SIGNAL ;
    PORT
      LAYER M1 ;
        RECT 0.224 0.028 0.28 0.348 ;
    END
  END Y
  PIN VDD
    DIRECTION INOUT ;
    USE POWER ;
    SHAPE ABUTMENT ;
    PORT
      LAYER BSM0 ;
        RECT 0 0.248 0.504 0.504 ;
    END
  END VDD
  PIN VSS
    DIRECTION INOUT ;
    USE GROUND ;
    SHAPE ABUTMENT ;
    PORT
      LAYER BSM0 ;
        RECT 0 -0.128 0.504 0.128 ;
    END
  END VSS
  OBS
    LAYER M0 ;
      RECT 0.208 0.04 0.464 0.084 ;
      RECT 0.292 0.124 0.464 0.168 ;
      RECT 0.04 0.292 0.464 0.336 ;
      RECT 0.04 0.124 0.212 0.168 ;
  END
END NAND2_x1

MACRO NAND2_x2
  CLASS CORE ;
  ORIGIN 0 0 ;
  FOREIGN NAND2_x2 0 0 ;
  SIZE 0.84 BY 0.376 ;
  SYMMETRY X Y ;
  SITE CoreSite ;
  PIN A
    DIRECTION INPUT ;
    USE SIGNAL ;
    PORT
      LAYER M1 ;
        RECT 0.056 0.028 0.112 0.348 ;
    END
  END A
  PIN B
    DIRECTION INPUT ;
    USE SIGNAL ;
    PORT
      LAYER M1 ;
        RECT 0.392 0.028 0.448 0.348 ;
    END
  END B
  PIN Y
    DIRECTION OUTPUT ;
    USE SIGNAL ;
    PORT
      LAYER M1 ;
        RECT 0.224 0.028 0.28 0.348 ;
    END
  END Y
  PIN VDD
    DIRECTION INOUT ;
    USE POWER ;
    SHAPE ABUTMENT ;
    PORT
      LAYER BSM0 ;
        RECT 0 0.248 0.84 0.504 ;
    END
  END VDD
  PIN VSS
    DIRECTION INOUT ;
    USE GROUND ;
    SHAPE ABUTMENT ;
    PORT
      LAYER BSM0 ;
        RECT 0 -0.128 0.84 0.128 ;
    END
  END VSS
  OBS
    LAYER M0 ;
      RECT 0.04 0.04 0.8 0.084 ;
      RECT 0.632 0.208 0.8 0.252 ;
      RECT 0.04 0.292 0.796 0.336 ;
      RECT 0.296 0.208 0.54 0.252 ;
      RECT 0.208 0.124 0.46 0.168 ;
      RECT 0.04 0.208 0.208 0.252 ;
    LAYER M1 ;
      RECT 0.728 0.028 0.784 0.348 ;
  END
END NAND2_x2

MACRO NAND2_x4
  CLASS CORE ;
  ORIGIN 0 0 ;
  FOREIGN NAND2_x4 0 0 ;
  SIZE 1.512 BY 0.376 ;
  SYMMETRY X Y ;
  SITE CoreSite ;
  PIN A
    DIRECTION INPUT ;
    USE SIGNAL ;
    PORT
      LAYER M1 ;
        RECT 0.224 0.028 0.28 0.348 ;
    END
  END A
  PIN B
    DIRECTION INPUT ;
    USE SIGNAL ;
    PORT
      LAYER M1 ;
        RECT 0.728 0.028 0.784 0.348 ;
    END
  END B
  PIN Y
    DIRECTION OUTPUT ;
    USE SIGNAL ;
    PORT
      LAYER M1 ;
        RECT 0.56 0.028 0.616 0.348 ;
    END
  END Y
  PIN VDD
    DIRECTION INOUT ;
    USE POWER ;
    SHAPE ABUTMENT ;
    PORT
      LAYER BSM0 ;
        RECT 0 0.248 1.512 0.504 ;
    END
  END VDD
  PIN VSS
    DIRECTION INOUT ;
    USE GROUND ;
    SHAPE ABUTMENT ;
    PORT
      LAYER BSM0 ;
        RECT 0 -0.128 1.512 0.128 ;
    END
  END VSS
  OBS
    LAYER M0 ;
      RECT 0.04 0.292 1.472 0.336 ;
      RECT 0.128 0.124 1.384 0.168 ;
      RECT 0.296 0.208 1.216 0.252 ;
      RECT 0.376 0.04 1.136 0.084 ;
  END
END NAND2_x4

MACRO NAND2_x6
  CLASS CORE ;
  ORIGIN 0 0 ;
  FOREIGN NAND2_x6 0 0 ;
  SIZE 2.184 BY 0.376 ;
  SYMMETRY X Y ;
  SITE CoreSite ;
  PIN A
    DIRECTION INPUT ;
    USE SIGNAL ;
    PORT
      LAYER M1 ;
        RECT 0.224 0.028 0.28 0.348 ;
    END
  END A
  PIN B
    DIRECTION INPUT ;
    USE SIGNAL ;
    PORT
      LAYER M1 ;
        RECT 0.728 0.028 0.784 0.348 ;
    END
  END B
  PIN Y
    DIRECTION OUTPUT ;
    USE SIGNAL ;
    PORT
      LAYER M1 ;
        RECT 0.56 0.028 0.616 0.348 ;
    END
  END Y
  PIN VDD
    DIRECTION INOUT ;
    USE POWER ;
    SHAPE ABUTMENT ;
    PORT
      LAYER BSM0 ;
        RECT 0 0.248 2.184 0.504 ;
    END
  END VDD
  PIN VSS
    DIRECTION INOUT ;
    USE GROUND ;
    SHAPE ABUTMENT ;
    PORT
      LAYER BSM0 ;
        RECT 0 -0.128 2.184 0.128 ;
    END
  END VSS
  OBS
    LAYER M0 ;
      RECT 0.04 0.292 2.144 0.336 ;
      RECT 0.128 0.124 2.056 0.168 ;
      RECT 0.296 0.208 1.888 0.252 ;
      RECT 0.376 0.04 1.808 0.084 ;
  END
END NAND2_x6

MACRO NAND3_x1
  CLASS CORE ;
  ORIGIN 0 0 ;
  FOREIGN NAND3_x1 0 0 ;
  SIZE 0.672 BY 0.376 ;
  SYMMETRY X Y ;
  SITE CoreSite ;
  PIN A
    DIRECTION INPUT ;
    USE SIGNAL ;
    PORT
      LAYER M1 ;
        RECT 0.56 0.028 0.616 0.348 ;
    END
  END A
  PIN B
    DIRECTION INPUT ;
    USE SIGNAL ;
    PORT
      LAYER M1 ;
        RECT 0.392 0.028 0.448 0.348 ;
    END
  END B
  PIN C
    DIRECTION INPUT ;
    USE SIGNAL ;
    PORT
      LAYER M1 ;
        RECT 0.224 0.028 0.28 0.348 ;
    END
  END C
  PIN Y
    DIRECTION OUTPUT ;
    USE SIGNAL ;
    PORT
      LAYER M1 ;
        RECT 0.056 0.028 0.112 0.348 ;
    END
  END Y
  PIN VDD
    DIRECTION INOUT ;
    USE POWER ;
    SHAPE ABUTMENT ;
    PORT
      LAYER BSM0 ;
        RECT 0 0.248 0.672 0.504 ;
    END
  END VDD
  PIN VSS
    DIRECTION INOUT ;
    USE GROUND ;
    SHAPE ABUTMENT ;
    PORT
      LAYER BSM0 ;
        RECT 0 -0.128 0.672 0.128 ;
    END
  END VSS
  OBS
    LAYER M0 ;
      RECT 0.464 0.124 0.628 0.168 ;
      RECT 0.3 0.208 0.46 0.252 ;
      RECT 0.04 0.292 0.456 0.336 ;
      RECT 0.128 0.124 0.292 0.168 ;
  END
END NAND3_x1

MACRO NAND3_x2
  CLASS CORE ;
  ORIGIN 0 0 ;
  FOREIGN NAND3_x2 0 0 ;
  SIZE 1.176 BY 0.376 ;
  SYMMETRY X Y ;
  SITE CoreSite ;
  PIN A
    DIRECTION INPUT ;
    USE SIGNAL ;
    PORT
      LAYER M1 ;
        RECT 0.56 0.028 0.616 0.348 ;
    END
  END A
  PIN B
    DIRECTION INPUT ;
    USE SIGNAL ;
    PORT
      LAYER M1 ;
        RECT 0.392 0.028 0.448 0.348 ;
    END
  END B
  PIN C
    DIRECTION INPUT ;
    USE SIGNAL ;
    PORT
      LAYER M1 ;
        RECT 0.224 0.028 0.28 0.348 ;
    END
  END C
  PIN Y
    DIRECTION OUTPUT ;
    USE SIGNAL ;
    PORT
      LAYER M1 ;
        RECT 0.728 0.028 0.784 0.348 ;
    END
  END Y
  PIN VDD
    DIRECTION INOUT ;
    USE POWER ;
    SHAPE ABUTMENT ;
    PORT
      LAYER BSM0 ;
        RECT 0 0.248 1.176 0.504 ;
    END
  END VDD
  PIN VSS
    DIRECTION INOUT ;
    USE GROUND ;
    SHAPE ABUTMENT ;
    PORT
      LAYER BSM0 ;
        RECT 0 -0.128 1.176 0.128 ;
    END
  END VSS
  OBS
    LAYER M0 ;
      RECT 0.04 0.292 1.136 0.336 ;
      RECT 0.128 0.04 1.048 0.084 ;
      RECT 0.296 0.124 0.88 0.168 ;
      RECT 0.464 0.208 0.712 0.252 ;
  END
END NAND3_x2

MACRO NAND3_x3
  CLASS CORE ;
  ORIGIN 0 0 ;
  FOREIGN NAND3_x3 0 0 ;
  SIZE 1.68 BY 0.376 ;
  SYMMETRY X Y ;
  SITE CoreSite ;
  PIN A
    DIRECTION INPUT ;
    USE SIGNAL ;
    PORT
      LAYER M1 ;
        RECT 0.56 0.028 0.616 0.348 ;
    END
  END A
  PIN B
    DIRECTION INPUT ;
    USE SIGNAL ;
    PORT
      LAYER M1 ;
        RECT 0.392 0.028 0.448 0.348 ;
    END
  END B
  PIN C
    DIRECTION INPUT ;
    USE SIGNAL ;
    PORT
      LAYER M1 ;
        RECT 0.224 0.028 0.28 0.348 ;
    END
  END C
  PIN Y
    DIRECTION OUTPUT ;
    USE SIGNAL ;
    PORT
      LAYER M1 ;
        RECT 0.728 0.028 0.784 0.348 ;
    END
  END Y
  PIN VDD
    DIRECTION INOUT ;
    USE POWER ;
    SHAPE ABUTMENT ;
    PORT
      LAYER BSM0 ;
        RECT 0 0.248 1.68 0.504 ;
    END
  END VDD
  PIN VSS
    DIRECTION INOUT ;
    USE GROUND ;
    SHAPE ABUTMENT ;
    PORT
      LAYER BSM0 ;
        RECT 0 -0.128 1.68 0.128 ;
    END
  END VSS
  OBS
    LAYER M0 ;
      RECT 0.04 0.292 1.64 0.336 ;
      RECT 0.464 0.208 1.552 0.252 ;
      RECT 0.296 0.124 1.384 0.168 ;
      RECT 0.128 0.04 1.216 0.084 ;
  END
END NAND3_x3

MACRO NAND3_x4
  CLASS CORE ;
  ORIGIN 0 0 ;
  FOREIGN NAND3_x4 0 0 ;
  SIZE 2.184 BY 0.376 ;
  SYMMETRY X Y ;
  SITE CoreSite ;
  PIN A
    DIRECTION INPUT ;
    USE SIGNAL ;
    PORT
      LAYER M1 ;
        RECT 0.56 0.028 0.616 0.348 ;
    END
  END A
  PIN B
    DIRECTION INPUT ;
    USE SIGNAL ;
    PORT
      LAYER M1 ;
        RECT 0.392 0.028 0.448 0.348 ;
    END
  END B
  PIN C
    DIRECTION INPUT ;
    USE SIGNAL ;
    PORT
      LAYER M1 ;
        RECT 0.224 0.028 0.28 0.348 ;
    END
  END C
  PIN Y
    DIRECTION OUTPUT ;
    USE SIGNAL ;
    PORT
      LAYER M1 ;
        RECT 0.728 0.028 0.784 0.348 ;
    END
  END Y
  PIN VDD
    DIRECTION INOUT ;
    USE POWER ;
    SHAPE ABUTMENT ;
    PORT
      LAYER BSM0 ;
        RECT 0 0.248 2.184 0.504 ;
    END
  END VDD
  PIN VSS
    DIRECTION INOUT ;
    USE GROUND ;
    SHAPE ABUTMENT ;
    PORT
      LAYER BSM0 ;
        RECT 0 -0.128 2.184 0.128 ;
    END
  END VSS
  OBS
    LAYER M0 ;
      RECT 0.04 0.292 2.144 0.336 ;
      RECT 0.128 0.04 2.056 0.084 ;
      RECT 0.296 0.124 1.888 0.168 ;
      RECT 0.464 0.208 1.72 0.252 ;
  END
END NAND3_x4

MACRO NAND4_x1
  CLASS CORE ;
  ORIGIN 0 0 ;
  FOREIGN NAND4_x1 0 0 ;
  SIZE 0.84 BY 0.376 ;
  SYMMETRY X Y ;
  SITE CoreSite ;
  PIN A
    DIRECTION INPUT ;
    USE SIGNAL ;
    PORT
      LAYER M1 ;
        RECT 0.224 0.028 0.28 0.348 ;
    END
  END A
  PIN B
    DIRECTION INPUT ;
    USE SIGNAL ;
    PORT
      LAYER M1 ;
        RECT 0.392 0.028 0.448 0.348 ;
    END
  END B
  PIN C
    DIRECTION INPUT ;
    USE SIGNAL ;
    PORT
      LAYER M1 ;
        RECT 0.56 0.028 0.616 0.348 ;
    END
  END C
  PIN D
    DIRECTION INPUT ;
    USE SIGNAL ;
    PORT
      LAYER M1 ;
        RECT 0.728 0.028 0.784 0.348 ;
    END
  END D
  PIN Y
    DIRECTION OUTPUT ;
    USE SIGNAL ;
    PORT
      LAYER M1 ;
        RECT 0.056 0.028 0.112 0.348 ;
    END
  END Y
  PIN VDD
    DIRECTION INOUT ;
    USE POWER ;
    SHAPE ABUTMENT ;
    PORT
      LAYER BSM0 ;
        RECT 0 0.248 0.84 0.504 ;
    END
  END VDD
  PIN VSS
    DIRECTION INOUT ;
    USE GROUND ;
    SHAPE ABUTMENT ;
    PORT
      LAYER BSM0 ;
        RECT 0 -0.128 0.84 0.128 ;
    END
  END VSS
  OBS
    LAYER M0 ;
      RECT 0.632 0.124 0.8 0.168 ;
      RECT 0.04 0.292 0.8 0.336 ;
      RECT 0.464 0.04 0.632 0.084 ;
      RECT 0.296 0.124 0.464 0.168 ;
      RECT 0.128 0.04 0.296 0.084 ;
  END
END NAND4_x1

MACRO NOR2_x1
  CLASS CORE ;
  ORIGIN 0 0 ;
  FOREIGN NOR2_x1 0 0 ;
  SIZE 0.504 BY 0.376 ;
  SYMMETRY X Y ;
  SITE CoreSite ;
  PIN A
    DIRECTION INPUT ;
    USE SIGNAL ;
    PORT
      LAYER M1 ;
        RECT 0.056 0.028 0.112 0.348 ;
    END
  END A
  PIN B
    DIRECTION INPUT ;
    USE SIGNAL ;
    PORT
      LAYER M1 ;
        RECT 0.392 0.028 0.448 0.348 ;
    END
  END B
  PIN Y
    DIRECTION OUTPUT ;
    USE SIGNAL ;
    PORT
      LAYER M1 ;
        RECT 0.224 0.028 0.28 0.348 ;
    END
  END Y
  PIN VDD
    DIRECTION INOUT ;
    USE POWER ;
    SHAPE ABUTMENT ;
    PORT
      LAYER BSM0 ;
        RECT 0 0.248 0.504 0.504 ;
    END
  END VDD
  PIN VSS
    DIRECTION INOUT ;
    USE GROUND ;
    SHAPE ABUTMENT ;
    PORT
      LAYER BSM0 ;
        RECT 0 -0.128 0.504 0.128 ;
    END
  END VSS
  OBS
    LAYER M0 ;
      RECT 0.04 0.04 0.464 0.084 ;
      RECT 0.3 0.124 0.464 0.168 ;
      RECT 0.208 0.292 0.464 0.336 ;
      RECT 0.04 0.124 0.208 0.168 ;
  END
END NOR2_x1

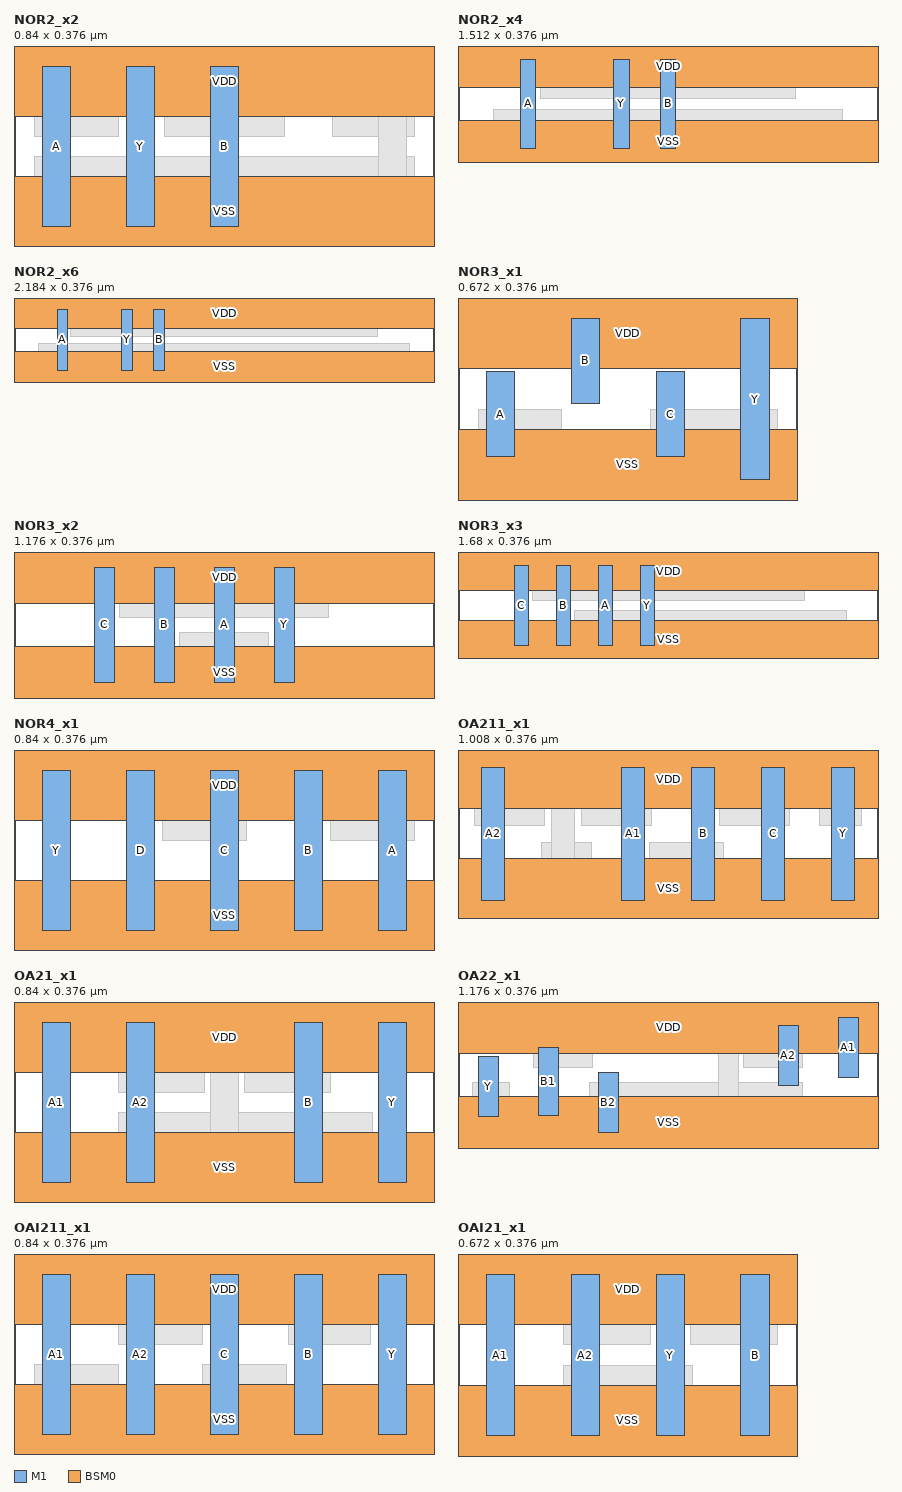
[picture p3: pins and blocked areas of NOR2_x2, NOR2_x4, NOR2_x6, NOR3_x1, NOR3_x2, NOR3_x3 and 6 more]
MACRO NOR2_x2
  CLASS CORE ;
  ORIGIN 0 0 ;
  FOREIGN NOR2_x2 0 0 ;
  SIZE 0.84 BY 0.376 ;
  SYMMETRY X Y ;
  SITE CoreSite ;
  PIN A
    DIRECTION INPUT ;
    USE SIGNAL ;
    PORT
      LAYER M1 ;
        RECT 0.056 0.028 0.112 0.348 ;
    END
  END A
  PIN B
    DIRECTION INPUT ;
    USE SIGNAL ;
    PORT
      LAYER M1 ;
        RECT 0.392 0.028 0.448 0.348 ;
    END
  END B
  PIN Y
    DIRECTION OUTPUT ;
    USE SIGNAL ;
    PORT
      LAYER M1 ;
        RECT 0.224 0.028 0.28 0.348 ;
    END
  END Y
  PIN VDD
    DIRECTION INOUT ;
    USE POWER ;
    SHAPE ABUTMENT ;
    PORT
      LAYER BSM0 ;
        RECT 0 0.248 0.84 0.504 ;
    END
  END VDD
  PIN VSS
    DIRECTION INOUT ;
    USE GROUND ;
    SHAPE ABUTMENT ;
    PORT
      LAYER BSM0 ;
        RECT 0 -0.128 0.84 0.128 ;
    END
  END VSS
  OBS
    LAYER M0 ;
      RECT 0.04 0.04 0.8 0.084 ;
      RECT 0.04 0.124 0.8 0.168 ;
      RECT 0.636 0.208 0.8 0.252 ;
      RECT 0.3 0.208 0.54 0.252 ;
      RECT 0.208 0.292 0.464 0.336 ;
      RECT 0.04 0.208 0.208 0.252 ;
    LAYER M1 ;
      RECT 0.728 0.028 0.784 0.348 ;
  END
END NOR2_x2

MACRO NOR2_x4
  CLASS CORE ;
  ORIGIN 0 0 ;
  FOREIGN NOR2_x4 0 0 ;
  SIZE 1.512 BY 0.376 ;
  SYMMETRY X Y ;
  SITE CoreSite ;
  PIN A
    DIRECTION INPUT ;
    USE SIGNAL ;
    PORT
      LAYER M1 ;
        RECT 0.224 0.028 0.28 0.348 ;
    END
  END A
  PIN B
    DIRECTION INPUT ;
    USE SIGNAL ;
    PORT
      LAYER M1 ;
        RECT 0.728 0.028 0.784 0.348 ;
    END
  END B
  PIN Y
    DIRECTION OUTPUT ;
    USE SIGNAL ;
    PORT
      LAYER M1 ;
        RECT 0.56 0.028 0.616 0.348 ;
    END
  END Y
  PIN VDD
    DIRECTION INOUT ;
    USE POWER ;
    SHAPE ABUTMENT ;
    PORT
      LAYER BSM0 ;
        RECT 0 0.248 1.512 0.504 ;
    END
  END VDD
  PIN VSS
    DIRECTION INOUT ;
    USE GROUND ;
    SHAPE ABUTMENT ;
    PORT
      LAYER BSM0 ;
        RECT 0 -0.128 1.512 0.128 ;
    END
  END VSS
  OBS
    LAYER M0 ;
      RECT 0.04 0.04 1.472 0.084 ;
      RECT 0.128 0.124 1.384 0.168 ;
      RECT 0.296 0.208 1.216 0.252 ;
      RECT 0.376 0.292 1.136 0.336 ;
  END
END NOR2_x4

MACRO NOR2_x6
  CLASS CORE ;
  ORIGIN 0 0 ;
  FOREIGN NOR2_x6 0 0 ;
  SIZE 2.184 BY 0.376 ;
  SYMMETRY X Y ;
  SITE CoreSite ;
  PIN A
    DIRECTION INPUT ;
    USE SIGNAL ;
    PORT
      LAYER M1 ;
        RECT 0.224 0.028 0.28 0.348 ;
    END
  END A
  PIN B
    DIRECTION INPUT ;
    USE SIGNAL ;
    PORT
      LAYER M1 ;
        RECT 0.728 0.028 0.784 0.348 ;
    END
  END B
  PIN Y
    DIRECTION OUTPUT ;
    USE SIGNAL ;
    PORT
      LAYER M1 ;
        RECT 0.56 0.028 0.616 0.348 ;
    END
  END Y
  PIN VDD
    DIRECTION INOUT ;
    USE POWER ;
    SHAPE ABUTMENT ;
    PORT
      LAYER BSM0 ;
        RECT 0 0.248 2.184 0.504 ;
    END
  END VDD
  PIN VSS
    DIRECTION INOUT ;
    USE GROUND ;
    SHAPE ABUTMENT ;
    PORT
      LAYER BSM0 ;
        RECT 0 -0.128 2.184 0.128 ;
    END
  END VSS
  OBS
    LAYER M0 ;
      RECT 0.04 0.04 2.144 0.084 ;
      RECT 0.128 0.124 2.056 0.168 ;
      RECT 0.296 0.208 1.888 0.252 ;
      RECT 0.376 0.292 1.808 0.336 ;
  END
END NOR2_x6

MACRO NOR3_x1
  CLASS CORE ;
  ORIGIN 0 0 ;
  FOREIGN NOR3_x1 0 0 ;
  SIZE 0.672 BY 0.376 ;
  SYMMETRY X Y ;
  SITE CoreSite ;
  PIN A
    DIRECTION INPUT ;
    USE SIGNAL ;
    PORT
      LAYER M1 ;
        RECT 0.056 0.074 0.112 0.242 ;
    END
  END A
  PIN B
    DIRECTION INPUT ;
    USE SIGNAL ;
    PORT
      LAYER M1 ;
        RECT 0.224 0.18 0.28 0.348 ;
    END
  END B
  PIN C
    DIRECTION INPUT ;
    USE SIGNAL ;
    PORT
      LAYER M1 ;
        RECT 0.392 0.074 0.448 0.242 ;
    END
  END C
  PIN Y
    DIRECTION OUTPUT ;
    USE SIGNAL ;
    PORT
      LAYER M1 ;
        RECT 0.56 0.028 0.616 0.348 ;
    END
  END Y
  PIN VDD
    DIRECTION INOUT ;
    USE POWER ;
    SHAPE ABUTMENT ;
    PORT
      LAYER BSM0 ;
        RECT 0 0.248 0.672 0.504 ;
    END
  END VDD
  PIN VSS
    DIRECTION INOUT ;
    USE GROUND ;
    SHAPE ABUTMENT ;
    PORT
      LAYER BSM0 ;
        RECT 0 -0.128 0.672 0.128 ;
    END
  END VSS
  OBS
    LAYER M0 ;
      RECT 0.38 0.124 0.632 0.168 ;
      RECT 0.048 0.04 0.628 0.084 ;
      RECT 0.464 0.292 0.628 0.336 ;
      RECT 0.212 0.292 0.386 0.336 ;
      RECT 0.04 0.124 0.204 0.168 ;
  END
END NOR3_x1

MACRO NOR3_x2
  CLASS CORE ;
  ORIGIN 0 0 ;
  FOREIGN NOR3_x2 0 0 ;
  SIZE 1.176 BY 0.376 ;
  SYMMETRY X Y ;
  SITE CoreSite ;
  PIN A
    DIRECTION INPUT ;
    USE SIGNAL ;
    PORT
      LAYER M1 ;
        RECT 0.56 0.028 0.616 0.348 ;
    END
  END A
  PIN B
    DIRECTION INPUT ;
    USE SIGNAL ;
    PORT
      LAYER M1 ;
        RECT 0.392 0.028 0.448 0.348 ;
    END
  END B
  PIN C
    DIRECTION INPUT ;
    USE SIGNAL ;
    PORT
      LAYER M1 ;
        RECT 0.224 0.028 0.28 0.348 ;
    END
  END C
  PIN Y
    DIRECTION OUTPUT ;
    USE SIGNAL ;
    PORT
      LAYER M1 ;
        RECT 0.728 0.028 0.784 0.348 ;
    END
  END Y
  PIN VDD
    DIRECTION INOUT ;
    USE POWER ;
    SHAPE ABUTMENT ;
    PORT
      LAYER BSM0 ;
        RECT 0 0.248 1.176 0.504 ;
    END
  END VDD
  PIN VSS
    DIRECTION INOUT ;
    USE GROUND ;
    SHAPE ABUTMENT ;
    PORT
      LAYER BSM0 ;
        RECT 0 -0.128 1.176 0.128 ;
    END
  END VSS
  OBS
    LAYER M0 ;
      RECT 0.04 0.04 1.136 0.084 ;
      RECT 0.128 0.292 1.048 0.336 ;
      RECT 0.296 0.208 0.88 0.252 ;
      RECT 0.464 0.124 0.712 0.168 ;
  END
END NOR3_x2

MACRO NOR3_x3
  CLASS CORE ;
  ORIGIN 0 0 ;
  FOREIGN NOR3_x3 0 0 ;
  SIZE 1.68 BY 0.376 ;
  SYMMETRY X Y ;
  SITE CoreSite ;
  PIN A
    DIRECTION INPUT ;
    USE SIGNAL ;
    PORT
      LAYER M1 ;
        RECT 0.56 0.028 0.616 0.348 ;
    END
  END A
  PIN B
    DIRECTION INPUT ;
    USE SIGNAL ;
    PORT
      LAYER M1 ;
        RECT 0.392 0.028 0.448 0.348 ;
    END
  END B
  PIN C
    DIRECTION INPUT ;
    USE SIGNAL ;
    PORT
      LAYER M1 ;
        RECT 0.224 0.028 0.28 0.348 ;
    END
  END C
  PIN Y
    DIRECTION OUTPUT ;
    USE SIGNAL ;
    PORT
      LAYER M1 ;
        RECT 0.728 0.028 0.784 0.348 ;
    END
  END Y
  PIN VDD
    DIRECTION INOUT ;
    USE POWER ;
    SHAPE ABUTMENT ;
    PORT
      LAYER BSM0 ;
        RECT 0 0.248 1.68 0.504 ;
    END
  END VDD
  PIN VSS
    DIRECTION INOUT ;
    USE GROUND ;
    SHAPE ABUTMENT ;
    PORT
      LAYER BSM0 ;
        RECT 0 -0.128 1.68 0.128 ;
    END
  END VSS
  OBS
    LAYER M0 ;
      RECT 0.04 0.04 1.64 0.084 ;
      RECT 0.464 0.124 1.552 0.168 ;
      RECT 0.296 0.208 1.384 0.252 ;
      RECT 0.128 0.292 1.216 0.336 ;
  END
END NOR3_x3

MACRO NOR4_x1
  CLASS CORE ;
  ORIGIN 0 0 ;
  FOREIGN NOR4_x1 0 0 ;
  SIZE 0.84 BY 0.376 ;
  SYMMETRY X Y ;
  SITE CoreSite ;
  PIN A
    DIRECTION INPUT ;
    USE SIGNAL ;
    PORT
      LAYER M1 ;
        RECT 0.728 0.028 0.784 0.348 ;
    END
  END A
  PIN B
    DIRECTION INPUT ;
    USE SIGNAL ;
    PORT
      LAYER M1 ;
        RECT 0.56 0.028 0.616 0.348 ;
    END
  END B
  PIN C
    DIRECTION INPUT ;
    USE SIGNAL ;
    PORT
      LAYER M1 ;
        RECT 0.392 0.028 0.448 0.348 ;
    END
  END C
  PIN D
    DIRECTION INPUT ;
    USE SIGNAL ;
    PORT
      LAYER M1 ;
        RECT 0.224 0.028 0.28 0.348 ;
    END
  END D
  PIN Y
    DIRECTION OUTPUT ;
    USE SIGNAL ;
    PORT
      LAYER M1 ;
        RECT 0.056 0.028 0.112 0.348 ;
    END
  END Y
  PIN VDD
    DIRECTION INOUT ;
    USE POWER ;
    SHAPE ABUTMENT ;
    PORT
      LAYER BSM0 ;
        RECT 0 0.248 0.84 0.504 ;
    END
  END VDD
  PIN VSS
    DIRECTION INOUT ;
    USE GROUND ;
    SHAPE ABUTMENT ;
    PORT
      LAYER BSM0 ;
        RECT 0 -0.128 0.84 0.128 ;
    END
  END VSS
  OBS
    LAYER M0 ;
      RECT 0.04 0.04 0.8 0.084 ;
      RECT 0.632 0.208 0.8 0.252 ;
      RECT 0.464 0.292 0.632 0.336 ;
      RECT 0.296 0.208 0.464 0.252 ;
      RECT 0.128 0.292 0.296 0.336 ;
  END
END NOR4_x1

MACRO OA211_x1
  CLASS CORE ;
  ORIGIN 0 0 ;
  FOREIGN OA211_x1 0 0 ;
  SIZE 1.008 BY 0.376 ;
  SYMMETRY X Y ;
  SITE CoreSite ;
  PIN A1
    DIRECTION INPUT ;
    USE SIGNAL ;
    PORT
      LAYER M1 ;
        RECT 0.392 0.028 0.448 0.348 ;
    END
  END A1
  PIN A2
    DIRECTION INPUT ;
    USE SIGNAL ;
    PORT
      LAYER M1 ;
        RECT 0.056 0.028 0.112 0.348 ;
    END
  END A2
  PIN B
    DIRECTION INPUT ;
    USE SIGNAL ;
    PORT
      LAYER M1 ;
        RECT 0.56 0.028 0.616 0.348 ;
    END
  END B
  PIN C
    DIRECTION INPUT ;
    USE SIGNAL ;
    PORT
      LAYER M1 ;
        RECT 0.728 0.028 0.784 0.348 ;
    END
  END C
  PIN Y
    DIRECTION OUTPUT ;
    USE SIGNAL ;
    PORT
      LAYER M1 ;
        RECT 0.896 0.028 0.952 0.348 ;
    END
  END Y
  PIN VDD
    DIRECTION INOUT ;
    USE POWER ;
    SHAPE ABUTMENT ;
    PORT
      LAYER BSM0 ;
        RECT 0 0.248 1.008 0.504 ;
    END
  END VDD
  PIN VSS
    DIRECTION INOUT ;
    USE GROUND ;
    SHAPE ABUTMENT ;
    PORT
      LAYER BSM0 ;
        RECT 0 -0.128 1.008 0.128 ;
    END
  END VSS
  OBS
    LAYER M0 ;
      RECT 0.868 0.04 0.968 0.084 ;
      RECT 0.868 0.208 0.968 0.252 ;
      RECT 0.04 0.292 0.884 0.336 ;
      RECT 0.628 0.208 0.796 0.252 ;
      RECT 0.46 0.124 0.636 0.168 ;
      RECT 0.04 0.04 0.468 0.084 ;
      RECT 0.296 0.208 0.464 0.252 ;
      RECT 0.2 0.124 0.32 0.168 ;
      RECT 0.04 0.208 0.208 0.252 ;
    LAYER M1 ;
      RECT 0.224 0.028 0.28 0.348 ;
  END
END OA211_x1

MACRO OA21_x1
  CLASS CORE ;
  ORIGIN 0 0 ;
  FOREIGN OA21_x1 0 0 ;
  SIZE 0.84 BY 0.376 ;
  SYMMETRY X Y ;
  SITE CoreSite ;
  PIN A1
    DIRECTION INPUT ;
    USE SIGNAL ;
    PORT
      LAYER M1 ;
        RECT 0.056 0.028 0.112 0.348 ;
    END
  END A1
  PIN A2
    DIRECTION INPUT ;
    USE SIGNAL ;
    PORT
      LAYER M1 ;
        RECT 0.224 0.028 0.28 0.348 ;
    END
  END A2
  PIN B
    DIRECTION INPUT ;
    USE SIGNAL ;
    PORT
      LAYER M1 ;
        RECT 0.56 0.028 0.616 0.348 ;
    END
  END B
  PIN Y
    DIRECTION OUTPUT ;
    USE SIGNAL ;
    PORT
      LAYER M1 ;
        RECT 0.728 0.028 0.784 0.348 ;
    END
  END Y
  PIN VDD
    DIRECTION INOUT ;
    USE POWER ;
    SHAPE ABUTMENT ;
    PORT
      LAYER BSM0 ;
        RECT 0 0.248 0.84 0.504 ;
    END
  END VDD
  PIN VSS
    DIRECTION INOUT ;
    USE GROUND ;
    SHAPE ABUTMENT ;
    PORT
      LAYER BSM0 ;
        RECT 0 -0.128 0.84 0.128 ;
    END
  END VSS
  OBS
    LAYER M0 ;
      RECT 0.688 0.04 0.8 0.084 ;
      RECT 0.688 0.292 0.8 0.336 ;
      RECT 0.208 0.124 0.716 0.168 ;
      RECT 0.46 0.208 0.632 0.252 ;
      RECT 0.352 0.292 0.472 0.336 ;
      RECT 0.04 0.04 0.464 0.084 ;
      RECT 0.208 0.208 0.38 0.252 ;
      RECT 0.04 0.292 0.212 0.336 ;
    LAYER M1 ;
      RECT 0.392 0.028 0.448 0.348 ;
  END
END OA21_x1

MACRO OA22_x1
  CLASS CORE ;
  ORIGIN 0 0 ;
  FOREIGN OA22_x1 0 0 ;
  SIZE 1.176 BY 0.376 ;
  SYMMETRY X Y ;
  SITE CoreSite ;
  PIN A1
    DIRECTION INPUT ;
    USE SIGNAL ;
    PORT
      LAYER M1 ;
        RECT 1.064 0.18 1.12 0.348 ;
    END
  END A1
  PIN A2
    DIRECTION INPUT ;
    USE SIGNAL ;
    PORT
      LAYER M1 ;
        RECT 0.896 0.158 0.952 0.326 ;
    END
  END A2
  PIN B1
    DIRECTION INPUT ;
    USE SIGNAL ;
    PORT
      LAYER M1 ;
        RECT 0.224 0.074 0.28 0.264 ;
    END
  END B1
  PIN B2
    DIRECTION INPUT ;
    USE SIGNAL ;
    PORT
      LAYER M1 ;
        RECT 0.392 0.028 0.448 0.196 ;
    END
  END B2
  PIN Y
    DIRECTION OUTPUT ;
    USE SIGNAL ;
    PORT
      LAYER M1 ;
        RECT 0.056 0.072 0.112 0.24 ;
    END
  END Y
  PIN VDD
    DIRECTION INOUT ;
    USE POWER ;
    SHAPE ABUTMENT ;
    PORT
      LAYER BSM0 ;
        RECT 0 0.248 1.176 0.504 ;
    END
  END VDD
  PIN VSS
    DIRECTION INOUT ;
    USE GROUND ;
    SHAPE ABUTMENT ;
    PORT
      LAYER BSM0 ;
        RECT 0 -0.128 1.176 0.128 ;
    END
  END VSS
  OBS
    LAYER M0 ;
      RECT 0.688 0.04 1.136 0.084 ;
      RECT 0.968 0.292 1.132 0.336 ;
      RECT 0.368 0.124 0.964 0.168 ;
      RECT 0.8 0.208 0.964 0.252 ;
      RECT 0.128 0.292 0.808 0.336 ;
      RECT 0.38 0.04 0.572 0.084 ;
      RECT 0.212 0.208 0.376 0.252 ;
      RECT 0.04 0.124 0.144 0.168 ;
    LAYER M1 ;
      RECT 0.728 0.028 0.784 0.348 ;
  END
  PROPERTY CatenaDesignType "deviceLevel" ;
  PROPERTY pkpIndependentSourceSHA256 "c547a8aa444d608dc216510e46f1f0709ec88807917adefe6256126d9f2918d8" ;
END OA22_x1

MACRO OAI211_x1
  CLASS CORE ;
  ORIGIN 0 0 ;
  FOREIGN OAI211_x1 0 0 ;
  SIZE 0.84 BY 0.376 ;
  SYMMETRY X Y ;
  SITE CoreSite ;
  PIN A1
    DIRECTION INPUT ;
    USE SIGNAL ;
    PORT
      LAYER M1 ;
        RECT 0.056 0.028 0.112 0.348 ;
    END
  END A1
  PIN A2
    DIRECTION INPUT ;
    USE SIGNAL ;
    PORT
      LAYER M1 ;
        RECT 0.224 0.028 0.28 0.348 ;
    END
  END A2
  PIN B
    DIRECTION INPUT ;
    USE SIGNAL ;
    PORT
      LAYER M1 ;
        RECT 0.56 0.028 0.616 0.348 ;
    END
  END B
  PIN C
    DIRECTION INPUT ;
    USE SIGNAL ;
    PORT
      LAYER M1 ;
        RECT 0.392 0.028 0.448 0.348 ;
    END
  END C
  PIN Y
    DIRECTION OUTPUT ;
    USE SIGNAL ;
    PORT
      LAYER M1 ;
        RECT 0.728 0.028 0.784 0.348 ;
    END
  END Y
  PIN VDD
    DIRECTION INOUT ;
    USE POWER ;
    SHAPE ABUTMENT ;
    PORT
      LAYER BSM0 ;
        RECT 0 0.248 0.84 0.504 ;
    END
  END VDD
  PIN VSS
    DIRECTION INOUT ;
    USE GROUND ;
    SHAPE ABUTMENT ;
    PORT
      LAYER BSM0 ;
        RECT 0 -0.128 0.84 0.128 ;
    END
  END VSS
  OBS
    LAYER M0 ;
      RECT 0.688 0.04 0.8 0.084 ;
      RECT 0.372 0.292 0.8 0.336 ;
      RECT 0.548 0.208 0.712 0.252 ;
      RECT 0.376 0.124 0.544 0.168 ;
      RECT 0.044 0.04 0.46 0.084 ;
      RECT 0.208 0.208 0.376 0.252 ;
      RECT 0.04 0.124 0.208 0.168 ;
  END
END OAI211_x1

MACRO OAI21_x1
  CLASS CORE ;
  ORIGIN 0 0 ;
  FOREIGN OAI21_x1 0 0 ;
  SIZE 0.672 BY 0.376 ;
  SYMMETRY X Y ;
  SITE CoreSite ;
  PIN A1
    DIRECTION INPUT ;
    USE SIGNAL ;
    PORT
      LAYER M1 ;
        RECT 0.056 0.028 0.112 0.348 ;
    END
  END A1
  PIN A2
    DIRECTION INPUT ;
    USE SIGNAL ;
    PORT
      LAYER M1 ;
        RECT 0.224 0.028 0.28 0.348 ;
    END
  END A2
  PIN B
    DIRECTION INPUT ;
    USE SIGNAL ;
    PORT
      LAYER M1 ;
        RECT 0.56 0.028 0.616 0.348 ;
    END
  END B
  PIN Y
    DIRECTION OUTPUT ;
    USE SIGNAL ;
    PORT
      LAYER M1 ;
        RECT 0.392 0.028 0.448 0.348 ;
    END
  END Y
  PIN VDD
    DIRECTION INOUT ;
    USE POWER ;
    SHAPE ABUTMENT ;
    PORT
      LAYER BSM0 ;
        RECT 0 0.248 0.672 0.504 ;
    END
  END VDD
  PIN VSS
    DIRECTION INOUT ;
    USE GROUND ;
    SHAPE ABUTMENT ;
    PORT
      LAYER BSM0 ;
        RECT 0 -0.128 0.672 0.128 ;
    END
  END VSS
  OBS
    LAYER M0 ;
      RECT 0.46 0.208 0.632 0.252 ;
      RECT 0.352 0.292 0.472 0.336 ;
      RECT 0.04 0.04 0.464 0.084 ;
      RECT 0.208 0.124 0.464 0.168 ;
      RECT 0.208 0.208 0.38 0.252 ;
      RECT 0.04 0.292 0.212 0.336 ;
  END
  PROPERTY CatenaDesignType "deviceLevel" ;
END OAI21_x1

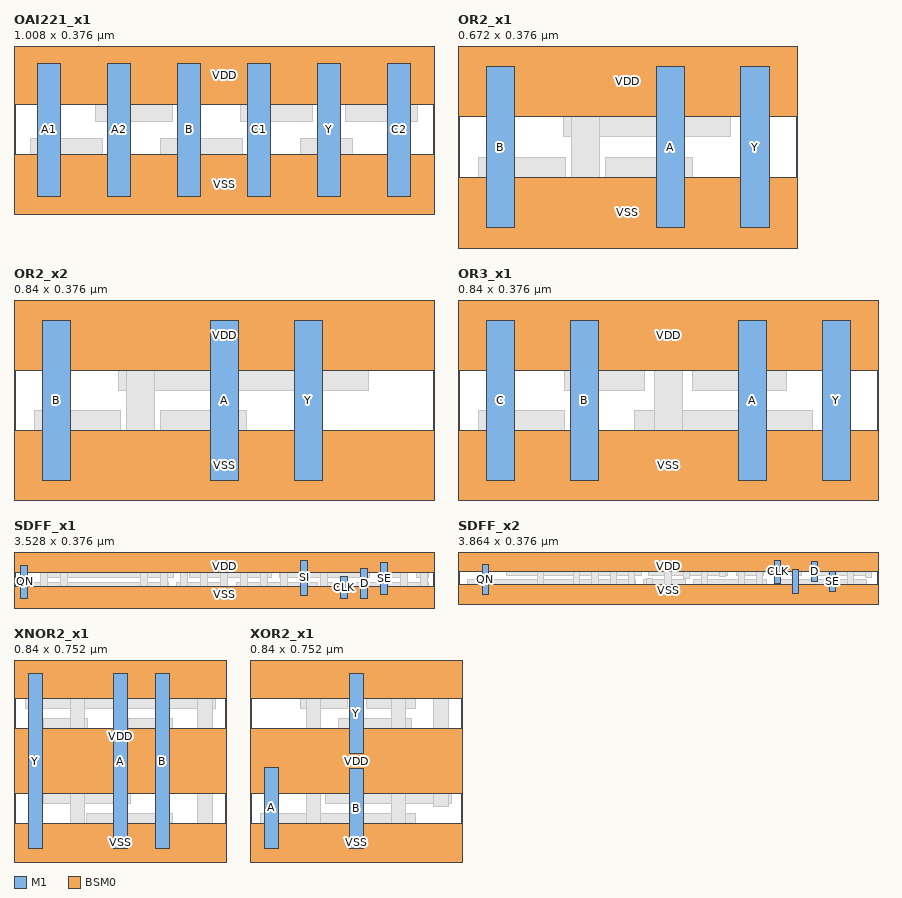
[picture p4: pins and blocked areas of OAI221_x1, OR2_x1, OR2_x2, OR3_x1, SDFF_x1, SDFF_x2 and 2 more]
MACRO OAI221_x1
  CLASS CORE ;
  ORIGIN 0 0 ;
  FOREIGN OAI221_x1 0 0 ;
  SIZE 1.008 BY 0.376 ;
  SYMMETRY X Y ;
  SITE CoreSite ;
  PIN A1
    DIRECTION INPUT ;
    USE SIGNAL ;
    PORT
      LAYER M1 ;
        RECT 0.056 0.028 0.112 0.348 ;
    END
  END A1
  PIN A2
    DIRECTION INPUT ;
    USE SIGNAL ;
    PORT
      LAYER M1 ;
        RECT 0.224 0.028 0.28 0.348 ;
    END
  END A2
  PIN B
    DIRECTION INPUT ;
    USE SIGNAL ;
    PORT
      LAYER M1 ;
        RECT 0.392 0.028 0.448 0.348 ;
    END
  END B
  PIN C1
    DIRECTION INPUT ;
    USE SIGNAL ;
    PORT
      LAYER M1 ;
        RECT 0.56 0.028 0.616 0.348 ;
    END
  END C1
  PIN C2
    DIRECTION INPUT ;
    USE SIGNAL ;
    PORT
      LAYER M1 ;
        RECT 0.896 0.028 0.952 0.348 ;
    END
  END C2
  PIN Y
    DIRECTION OUTPUT ;
    USE SIGNAL ;
    PORT
      LAYER M1 ;
        RECT 0.728 0.028 0.784 0.348 ;
    END
  END Y
  PIN VDD
    DIRECTION INOUT ;
    USE POWER ;
    SHAPE ABUTMENT ;
    PORT
      LAYER BSM0 ;
        RECT 0 0.248 1.008 0.504 ;
    END
  END VDD
  PIN VSS
    DIRECTION INOUT ;
    USE GROUND ;
    SHAPE ABUTMENT ;
    PORT
      LAYER BSM0 ;
        RECT 0 -0.128 1.008 0.128 ;
    END
  END VSS
  OBS
    LAYER M0 ;
      RECT 0.548 0.04 0.968 0.084 ;
      RECT 0.796 0.208 0.968 0.252 ;
      RECT 0.376 0.292 0.968 0.336 ;
      RECT 0.688 0.124 0.812 0.168 ;
      RECT 0.544 0.208 0.716 0.252 ;
      RECT 0.352 0.124 0.548 0.168 ;
      RECT 0.04 0.04 0.46 0.084 ;
      RECT 0.196 0.208 0.38 0.252 ;
      RECT 0.04 0.124 0.212 0.168 ;
  END
END OAI221_x1

MACRO OR2_x1
  CLASS CORE ;
  ORIGIN 0 0 ;
  FOREIGN OR2_x1 0 0 ;
  SIZE 0.672 BY 0.376 ;
  SYMMETRY X Y ;
  SITE CoreSite ;
  PIN A
    DIRECTION INPUT ;
    USE SIGNAL ;
    PORT
      LAYER M1 ;
        RECT 0.392 0.028 0.448 0.348 ;
    END
  END A
  PIN B
    DIRECTION INPUT ;
    USE SIGNAL ;
    PORT
      LAYER M1 ;
        RECT 0.056 0.028 0.112 0.348 ;
    END
  END B
  PIN Y
    DIRECTION OUTPUT ;
    USE SIGNAL ;
    PORT
      LAYER M1 ;
        RECT 0.56 0.028 0.616 0.348 ;
    END
  END Y
  PIN VDD
    DIRECTION INOUT ;
    USE POWER ;
    SHAPE ABUTMENT ;
    PORT
      LAYER BSM0 ;
        RECT 0 0.248 0.672 0.504 ;
    END
  END VDD
  PIN VSS
    DIRECTION INOUT ;
    USE GROUND ;
    SHAPE ABUTMENT ;
    PORT
      LAYER BSM0 ;
        RECT 0 -0.128 0.672 0.128 ;
    END
  END VSS
  OBS
    LAYER M0 ;
      RECT 0.532 0.04 0.632 0.084 ;
      RECT 0.532 0.292 0.632 0.336 ;
      RECT 0.208 0.208 0.54 0.252 ;
      RECT 0.292 0.124 0.464 0.168 ;
      RECT 0.2 0.04 0.32 0.084 ;
      RECT 0.04 0.292 0.32 0.336 ;
      RECT 0.04 0.124 0.212 0.168 ;
    LAYER M1 ;
      RECT 0.224 0.028 0.28 0.348 ;
  END
END OR2_x1

MACRO OR2_x2
  CLASS CORE ;
  ORIGIN 0 0 ;
  FOREIGN OR2_x2 0 0 ;
  SIZE 0.84 BY 0.376 ;
  SYMMETRY X Y ;
  SITE CoreSite ;
  PIN A
    DIRECTION INPUT ;
    USE SIGNAL ;
    PORT
      LAYER M1 ;
        RECT 0.392 0.028 0.448 0.348 ;
    END
  END A
  PIN B
    DIRECTION INPUT ;
    USE SIGNAL ;
    PORT
      LAYER M1 ;
        RECT 0.056 0.028 0.112 0.348 ;
    END
  END B
  PIN Y
    DIRECTION OUTPUT ;
    USE SIGNAL ;
    PORT
      LAYER M1 ;
        RECT 0.56 0.028 0.616 0.348 ;
    END
  END Y
  PIN VDD
    DIRECTION INOUT ;
    USE POWER ;
    SHAPE ABUTMENT ;
    PORT
      LAYER BSM0 ;
        RECT 0 0.248 0.84 0.504 ;
    END
  END VDD
  PIN VSS
    DIRECTION INOUT ;
    USE GROUND ;
    SHAPE ABUTMENT ;
    PORT
      LAYER BSM0 ;
        RECT 0 -0.128 0.84 0.128 ;
    END
  END VSS
  OBS
    LAYER M0 ;
      RECT 0.208 0.208 0.708 0.252 ;
      RECT 0.536 0.04 0.656 0.084 ;
      RECT 0.536 0.292 0.656 0.336 ;
      RECT 0.292 0.124 0.464 0.168 ;
      RECT 0.2 0.04 0.32 0.084 ;
      RECT 0.04 0.292 0.32 0.336 ;
      RECT 0.04 0.124 0.212 0.168 ;
    LAYER M1 ;
      RECT 0.224 0.028 0.28 0.348 ;
  END
END OR2_x2

MACRO OR3_x1
  CLASS CORE ;
  ORIGIN 0 0 ;
  FOREIGN OR3_x1 0 0 ;
  SIZE 0.84 BY 0.376 ;
  SYMMETRY X Y ;
  SITE CoreSite ;
  PIN A
    DIRECTION INPUT ;
    USE SIGNAL ;
    PORT
      LAYER M1 ;
        RECT 0.56 0.028 0.616 0.348 ;
    END
  END A
  PIN B
    DIRECTION INPUT ;
    USE SIGNAL ;
    PORT
      LAYER M1 ;
        RECT 0.224 0.028 0.28 0.348 ;
    END
  END B
  PIN C
    DIRECTION INPUT ;
    USE SIGNAL ;
    PORT
      LAYER M1 ;
        RECT 0.056 0.028 0.112 0.348 ;
    END
  END C
  PIN Y
    DIRECTION OUTPUT ;
    USE SIGNAL ;
    PORT
      LAYER M1 ;
        RECT 0.728 0.028 0.784 0.348 ;
    END
  END Y
  PIN VDD
    DIRECTION INOUT ;
    USE POWER ;
    SHAPE ABUTMENT ;
    PORT
      LAYER BSM0 ;
        RECT 0 0.248 0.84 0.504 ;
    END
  END VDD
  PIN VSS
    DIRECTION INOUT ;
    USE GROUND ;
    SHAPE ABUTMENT ;
    PORT
      LAYER BSM0 ;
        RECT 0 -0.128 0.84 0.128 ;
    END
  END VSS
  OBS
    LAYER M0 ;
      RECT 0.688 0.04 0.8 0.084 ;
      RECT 0.688 0.292 0.8 0.336 ;
      RECT 0.352 0.124 0.708 0.168 ;
      RECT 0.468 0.208 0.656 0.252 ;
      RECT 0.044 0.04 0.472 0.084 ;
      RECT 0.04 0.292 0.472 0.336 ;
      RECT 0.212 0.208 0.372 0.252 ;
      RECT 0.04 0.124 0.212 0.168 ;
    LAYER M1 ;
      RECT 0.392 0.028 0.448 0.348 ;
  END
END OR3_x1

MACRO SDFF_x1
  CLASS CORE ;
  ORIGIN 0 0 ;
  FOREIGN SDFF_x1 0 0 ;
  SIZE 3.528 BY 0.376 ;
  SYMMETRY X Y ;
  SITE CoreSite ;
  PIN CLK
    DIRECTION INPUT ;
    USE CLOCK ;
    PORT
      LAYER M1 ;
        RECT 2.744 0.028 2.8 0.218 ;
    END
  END CLK
  PIN D
    DIRECTION INPUT ;
    USE SIGNAL ;
    PORT
      LAYER M1 ;
        RECT 2.912 0.028 2.968 0.284 ;
    END
  END D
  PIN QN
    DIRECTION OUTPUT ;
    USE SIGNAL ;
    PORT
      LAYER M1 ;
        RECT 0.056 0.028 0.112 0.31 ;
    END
  END QN
  PIN SE
    DIRECTION INPUT ;
    USE SIGNAL ;
    PORT
      LAYER M1 ;
        RECT 3.08 0.06 3.136 0.334 ;
    END
  END SE
  PIN SI
    DIRECTION INPUT ;
    USE SIGNAL ;
    PORT
      LAYER M1 ;
        RECT 2.408 0.058 2.464 0.348 ;
    END
  END SI
  PIN VDD
    DIRECTION INOUT ;
    USE POWER ;
    SHAPE ABUTMENT ;
    PORT
      LAYER BSM0 ;
        RECT 0 0.248 3.528 0.504 ;
    END
  END VDD
  PIN VSS
    DIRECTION INOUT ;
    USE GROUND ;
    SHAPE ABUTMENT ;
    PORT
      LAYER BSM0 ;
        RECT 0 -0.128 3.528 0.128 ;
    END
  END VSS
  OBS
    LAYER M0 ;
      RECT 3.156 0.04 3.488 0.084 ;
      RECT 2.626 0.124 3.484 0.168 ;
      RECT 2.82 0.292 3.484 0.336 ;
      RECT 3.38 0.208 3.48 0.252 ;
      RECT 3.056 0.208 3.258 0.252 ;
      RECT 2.9 0.04 3.078 0.084 ;
      RECT 2.232 0.208 2.982 0.252 ;
      RECT 2.46 0.04 2.828 0.084 ;
      RECT 2.394 0.292 2.748 0.336 ;
      RECT 1.866 0.124 2.552 0.168 ;
      RECT 1.22 0.04 2.364 0.084 ;
      RECT 2.148 0.292 2.322 0.336 ;
      RECT 1.476 0.208 2.16 0.252 ;
      RECT 0.538 0.292 2.076 0.336 ;
      RECT 1.368 0.124 1.742 0.168 ;
      RECT 0.258 0.208 1.336 0.252 ;
      RECT 0.064 0.124 1.296 0.168 ;
      RECT 0.968 0.04 1.144 0.084 ;
      RECT 0.376 0.04 0.894 0.084 ;
      RECT 0.366 0.292 0.466 0.336 ;
      RECT 0.076 0.292 0.294 0.336 ;
      RECT 0.04 0.04 0.24 0.084 ;
    LAYER M1 ;
      RECT 3.416 0.028 3.472 0.348 ;
      RECT 3.248 0.028 3.304 0.334 ;
      RECT 2.576 0.13 2.632 0.342 ;
      RECT 2.24 0.028 2.296 0.348 ;
      RECT 2.072 0.048 2.128 0.348 ;
      RECT 1.904 0.03 1.96 0.348 ;
      RECT 1.736 0.06 1.792 0.284 ;
      RECT 1.568 0.032 1.624 0.308 ;
      RECT 1.4 0.028 1.456 0.336 ;
      RECT 1.232 0.028 1.288 0.348 ;
      RECT 1.064 0.028 1.12 0.348 ;
      RECT 0.392 0.028 0.448 0.348 ;
      RECT 0.224 0.1 0.28 0.348 ;
  END
END SDFF_x1

MACRO SDFF_x2
  CLASS CORE ;
  ORIGIN 0 0 ;
  FOREIGN SDFF_x2 0 0 ;
  SIZE 3.864 BY 0.376 ;
  SYMMETRY X Y ;
  SITE CoreSite ;
  PIN CLK
    DIRECTION INPUT ;
    USE CLOCK ;
    PORT
      LAYER M1 ;
        RECT 2.912 0.136 2.968 0.348 ;
    END
  END CLK
  PIN D
    DIRECTION INPUT ;
    USE SIGNAL ;
    PORT
      LAYER M1 ;
        RECT 3.248 0.156 3.304 0.334 ;
    END
  END D
  PIN QN
    DIRECTION OUTPUT ;
    USE SIGNAL ;
    PORT
      LAYER M1 ;
        RECT 0.224 0.028 0.28 0.306 ;
    END
  END QN
  PIN SE
    DIRECTION INPUT ;
    USE SIGNAL ;
    PORT
      LAYER M1 ;
        RECT 3.416 0.062 3.472 0.242 ;
    END
  END SE
  PIN SI
    DIRECTION INPUT ;
    USE SIGNAL ;
    PORT
      LAYER M1 ;
        RECT 3.08 0.042 3.136 0.264 ;
    END
  END SI
  PIN VDD
    DIRECTION INOUT ;
    USE POWER ;
    SHAPE ABUTMENT ;
    PORT
      LAYER BSM0 ;
        RECT 0 0.248 3.864 0.504 ;
    END
  END VDD
  PIN VSS
    DIRECTION INOUT ;
    USE GROUND ;
    SHAPE ABUTMENT ;
    PORT
      LAYER BSM0 ;
        RECT 0 -0.128 3.864 0.128 ;
    END
  END VSS
  OBS
    LAYER M0 ;
      RECT 3.062 0.292 3.824 0.336 ;
      RECT 3.47 0.04 3.822 0.084 ;
      RECT 3.482 0.208 3.756 0.252 ;
      RECT 2.912 0.124 3.754 0.168 ;
      RECT 3.236 0.208 3.404 0.252 ;
      RECT 2.72 0.04 3.358 0.084 ;
      RECT 2.974 0.208 3.16 0.252 ;
      RECT 2.82 0.292 2.982 0.336 ;
      RECT 2.162 0.124 2.84 0.168 ;
      RECT 2.56 0.208 2.814 0.252 ;
      RECT 2.482 0.292 2.7 0.336 ;
      RECT 1.548 0.04 2.648 0.084 ;
      RECT 1.756 0.208 2.476 0.252 ;
      RECT 0.97 0.292 2.406 0.336 ;
      RECT 1.706 0.124 2.09 0.168 ;
      RECT 0.448 0.208 1.684 0.252 ;
      RECT 0.09 0.124 1.632 0.168 ;
      RECT 1.296 0.04 1.476 0.084 ;
      RECT 0.714 0.04 1.222 0.084 ;
      RECT 0.124 0.292 0.894 0.336 ;
      RECT 0.144 0.04 0.602 0.084 ;
    LAYER M1 ;
      RECT 3.752 0.188 3.808 0.348 ;
      RECT 3.584 0.112 3.64 0.302 ;
      RECT 2.744 0.028 2.8 0.29 ;
      RECT 2.576 0.028 2.632 0.348 ;
      RECT 2.408 0.196 2.464 0.344 ;
      RECT 2.24 0.054 2.296 0.348 ;
      RECT 2.072 0.176 2.128 0.348 ;
      RECT 1.904 0.08 1.96 0.348 ;
      RECT 1.736 0.036 1.792 0.184 ;
      RECT 1.568 0.028 1.624 0.298 ;
      RECT 1.4 0.028 1.456 0.348 ;
      RECT 1.232 0.122 1.288 0.348 ;
      RECT 1.064 0.028 1.12 0.326 ;
      RECT 0.728 0.084 0.784 0.348 ;
  END
END SDFF_x2

MACRO XNOR2_x1
  CLASS CORE ;
  ORIGIN 0 0 ;
  FOREIGN XNOR2_x1 0 0 ;
  SIZE 0.84 BY 0.752 ;
  SYMMETRY X Y ;
  SITE CoreSite ;
  PIN A
    DIRECTION INPUT ;
    USE SIGNAL ;
    PORT
      LAYER M1 ;
        RECT 0.392 0.028 0.448 0.724 ;
    END
  END A
  PIN B
    DIRECTION INPUT ;
    USE SIGNAL ;
    PORT
      LAYER M1 ;
        RECT 0.56 0.028 0.616 0.724 ;
    END
  END B
  PIN Y
    DIRECTION OUTPUT ;
    USE SIGNAL ;
    PORT
      LAYER M1 ;
        RECT 0.056 0.028 0.112 0.724 ;
    END
  END Y
  PIN VDD
    DIRECTION INOUT ;
    USE POWER ;
    SHAPE ABUTMENT ;
    PORT
      LAYER BSM0 ;
        RECT 0 0.248 0.84 0.504 ;
    END
  END VDD
  PIN VSS
    DIRECTION INOUT ;
    USE GROUND ;
    SHAPE ABUTMENT ;
    PORT
      LAYER BSM0 ;
        RECT 0 -0.128 0.84 0.128 ;
        RECT 0 0.624 0.84 0.88 ;
    END
  END VSS
  OBS
    LAYER M0 ;
      RECT 0.538 0.416 0.796 0.46 ;
      RECT 0.044 0.584 0.796 0.628 ;
      RECT 0.286 0.124 0.628 0.168 ;
      RECT 0.454 0.5 0.628 0.544 ;
      RECT 0.216 0.668 0.624 0.712 ;
      RECT 0.212 0.04 0.47 0.084 ;
      RECT 0.118 0.208 0.46 0.252 ;
      RECT 0.286 0.416 0.46 0.46 ;
      RECT 0.048 0.292 0.456 0.336 ;
      RECT 0.118 0.5 0.292 0.544 ;
      RECT 0.04 0.416 0.14 0.46 ;
    LAYER M1 ;
      RECT 0.728 0.028 0.784 0.724 ;
      RECT 0.224 0.028 0.28 0.724 ;
  END
END XNOR2_x1

MACRO XOR2_x1
  CLASS CORE ;
  ORIGIN 0 0 ;
  FOREIGN XOR2_x1 0 0 ;
  SIZE 0.84 BY 0.752 ;
  SYMMETRY X Y ;
  SITE CoreSite ;
  PIN A
    DIRECTION INPUT ;
    USE SIGNAL ;
    PORT
      LAYER M1 ;
        RECT 0.056 0.028 0.112 0.352 ;
    END
  END A
  PIN B
    DIRECTION INPUT ;
    USE SIGNAL ;
    PORT
      LAYER M1 ;
        RECT 0.392 0.028 0.448 0.348 ;
    END
  END B
  PIN Y
    DIRECTION OUTPUT ;
    USE SIGNAL ;
    PORT
      LAYER M1 ;
        RECT 0.392 0.404 0.448 0.724 ;
    END
  END Y
  PIN VDD
    DIRECTION INOUT ;
    USE POWER ;
    SHAPE ABUTMENT ;
    PORT
      LAYER BSM0 ;
        RECT 0 0.248 0.84 0.504 ;
    END
  END VDD
  PIN VSS
    DIRECTION INOUT ;
    USE GROUND ;
    SHAPE ABUTMENT ;
    PORT
      LAYER BSM0 ;
        RECT 0 -0.128 0.84 0.128 ;
        RECT 0 0.624 0.84 0.88 ;
    END
  END VSS
  OBS
    LAYER M0 ;
      RECT 0.368 0.416 0.8 0.46 ;
      RECT 0.632 0.668 0.8 0.712 ;
      RECT 0.3 0.208 0.796 0.252 ;
      RECT 0.04 0.124 0.656 0.168 ;
      RECT 0.46 0.584 0.656 0.628 ;
      RECT 0.352 0.5 0.64 0.544 ;
      RECT 0.352 0.668 0.472 0.712 ;
      RECT 0.04 0.04 0.464 0.084 ;
      RECT 0.208 0.292 0.464 0.336 ;
      RECT 0.2 0.584 0.384 0.628 ;
    LAYER M1 ;
      RECT 0.728 0.196 0.784 0.724 ;
      RECT 0.56 0.112 0.616 0.724 ;
      RECT 0.224 0.028 0.28 0.724 ;
  END
END XOR2_x1

END LIBRARY
